VERSION 5.6 ;

BUSBITCHARS "[]" ;

DIVIDERCHAR "/" ;

UNITS
    DATABASE MICRONS 1000 ;
END UNITS

MANUFACTURINGGRID 0.005000 ; 

CLEARANCEMEASURE EUCLIDEAN ; 

USEMINSPACING OBS ON ; 

SITE CoreSite
    CLASS CORE ;
    SIZE 0.600000 BY 0.300000 ;
END CoreSite

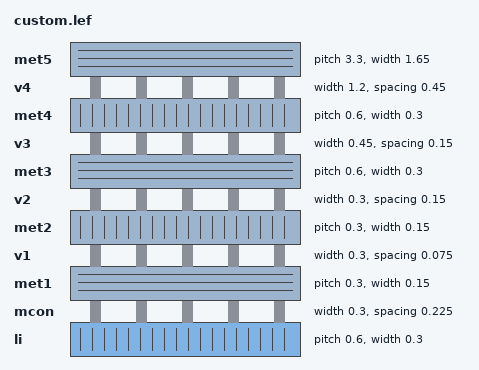
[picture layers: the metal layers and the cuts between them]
LAYER li
   TYPE ROUTING ;
   DIRECTION VERTICAL ;
   MINWIDTH 0.300000 ;
   AREA 0.056250 ;
   WIDTH 0.300000 ;
   SPACINGTABLE
      PARALLELRUNLENGTH 0.0
      WIDTH 0.0 0.225000 ;
   PITCH 0.600000 0.600000 ;
END li

LAYER mcon
    TYPE CUT ;
    SPACING 0.225000 ;
    WIDTH 0.300000 ;
    ENCLOSURE ABOVE 0.075000 0.075000 ;
    ENCLOSURE BELOW 0.000000 0.000000 ;
END mcon

LAYER met1
   TYPE ROUTING ;
   DIRECTION HORIZONTAL ;
   MINWIDTH 0.150000 ;
   AREA 0.084375 ;
   WIDTH 0.150000 ;
   SPACINGTABLE
      PARALLELRUNLENGTH 0.0
      WIDTH 0.0 0.150000 ;
   PITCH 0.300000 0.300000 ;
END met1

LAYER v1
    TYPE CUT ;
    SPACING 0.075000 ;
    WIDTH 0.300000 ;
    ENCLOSURE ABOVE 0.075000 0.075000 ;
    ENCLOSURE BELOW 0.075000 0.075000 ;
END v1

LAYER met2
   TYPE ROUTING ;
   DIRECTION VERTICAL ;
   MINWIDTH 0.150000 ;
   AREA 0.073125 ;
   WIDTH 0.150000 ;
   SPACINGTABLE
      PARALLELRUNLENGTH 0.0
      WIDTH 0.0 0.150000 ;
   PITCH 0.300000 0.300000 ;
END met2

LAYER v2
    TYPE CUT ;
    SPACING 0.150000 ;
    WIDTH 0.300000 ;
    ENCLOSURE ABOVE 0.075000 0.075000 ;
    ENCLOSURE BELOW 0.075000 0.000000 ;
END v2

LAYER met3
   TYPE ROUTING ;
   DIRECTION HORIZONTAL ;
   MINWIDTH 0.300000 ;
   AREA 0.241875 ;
   WIDTH 0.300000 ;
   SPACINGTABLE
      PARALLELRUNLENGTH 0.0
      WIDTH 0.0 0.300000 ;
   PITCH 0.600000 0.600000 ;
END met3

LAYER v3
    TYPE CUT ;
    SPACING 0.150000 ;
    WIDTH 0.450000 ;
    ENCLOSURE ABOVE 0.075000 0.075000 ;
    ENCLOSURE BELOW 0.075000 0.000000 ;
END v3

LAYER met4
   TYPE ROUTING ;
   DIRECTION VERTICAL ;
   MINWIDTH 0.300000 ;
   AREA 0.241875 ;
   WIDTH 0.300000 ;
   SPACINGTABLE
      PARALLELRUNLENGTH 0.0
      WIDTH 0.0 0.300000 ;
   PITCH 0.600000 0.600000 ;
END met4

LAYER v4
    TYPE CUT ;
    SPACING 0.450000 ;
    WIDTH 1.200000 ;
    ENCLOSURE ABOVE 0.150000 0.150000 ;
    ENCLOSURE BELOW 0.000000 0.000000 ;
END v4

LAYER met5
   TYPE ROUTING ;
   DIRECTION HORIZONTAL ;
   MINWIDTH 1.650000 ;
   AREA 4.005000 ;
   WIDTH 1.650000 ;
   SPACINGTABLE
      PARALLELRUNLENGTH 0.0
      WIDTH 0.0 1.650000 ;
   PITCH 3.300000 3.300000 ;
END met5

LAYER OVERLAP
   TYPE OVERLAP ;
END OVERLAP

VIA mcon_C DEFAULT
   LAYER li ;
     RECT -0.150000 -0.150000 0.150000 0.150000 ;
   LAYER mcon ;
     RECT -0.150000 -0.150000 0.150000 0.150000 ;
   LAYER met1 ;
     RECT -0.225000 -0.225000 0.225000 0.225000 ;
END mcon_C

VIA v1_C DEFAULT
   LAYER met1 ;
     RECT -0.225000 -0.225000 0.225000 0.225000 ;
   LAYER v1 ;
     RECT -0.150000 -0.150000 0.150000 0.150000 ;
   LAYER met2 ;
     RECT -0.225000 -0.225000 0.225000 0.225000 ;
END v1_C

VIA v2_C DEFAULT
   LAYER met2 ;
     RECT -0.150000 -0.225000 0.150000 0.225000 ;
   LAYER v2 ;
     RECT -0.150000 -0.150000 0.150000 0.150000 ;
   LAYER met3 ;
     RECT -0.225000 -0.225000 0.225000 0.225000 ;
END v2_C

VIA v2_Ch
   LAYER met2 ;
     RECT -0.225000 -0.150000 0.225000 0.150000 ;
   LAYER v2 ;
     RECT -0.150000 -0.150000 0.150000 0.150000 ;
   LAYER met3 ;
     RECT -0.225000 -0.225000 0.225000 0.225000 ;
END v2_Ch

VIA v2_Cv
   LAYER met2 ;
     RECT -0.150000 -0.225000 0.150000 0.225000 ;
   LAYER v2 ;
     RECT -0.150000 -0.150000 0.150000 0.150000 ;
   LAYER met3 ;
     RECT -0.225000 -0.225000 0.225000 0.225000 ;
END v2_Cv

VIA v3_C DEFAULT
   LAYER met3 ;
     RECT -0.300000 -0.225000 0.300000 0.225000 ;
   LAYER v3 ;
     RECT -0.225000 -0.225000 0.225000 0.225000 ;
   LAYER met4 ;
     RECT -0.300000 -0.300000 0.300000 0.300000 ;
END v3_C

VIA v3_Ch
   LAYER met3 ;
     RECT -0.300000 -0.225000 0.300000 0.225000 ;
   LAYER v3 ;
     RECT -0.225000 -0.225000 0.225000 0.225000 ;
   LAYER met4 ;
     RECT -0.300000 -0.300000 0.300000 0.300000 ;
END v3_Ch

VIA v3_Cv
   LAYER met3 ;
     RECT -0.300000 -0.225000 0.300000 0.225000 ;
   LAYER v3 ;
     RECT -0.225000 -0.225000 0.225000 0.225000 ;
   LAYER met4 ;
     RECT -0.300000 -0.300000 0.300000 0.300000 ;
END v3_Cv

VIA v4_C DEFAULT
   LAYER met4 ;
     RECT -0.600000 -0.600000 0.600000 0.600000 ;
   LAYER v4 ;
     RECT -0.600000 -0.600000 0.600000 0.600000 ;
   LAYER met5 ;
     RECT -0.750000 -0.750000 0.750000 0.750000 ;
END v4_C

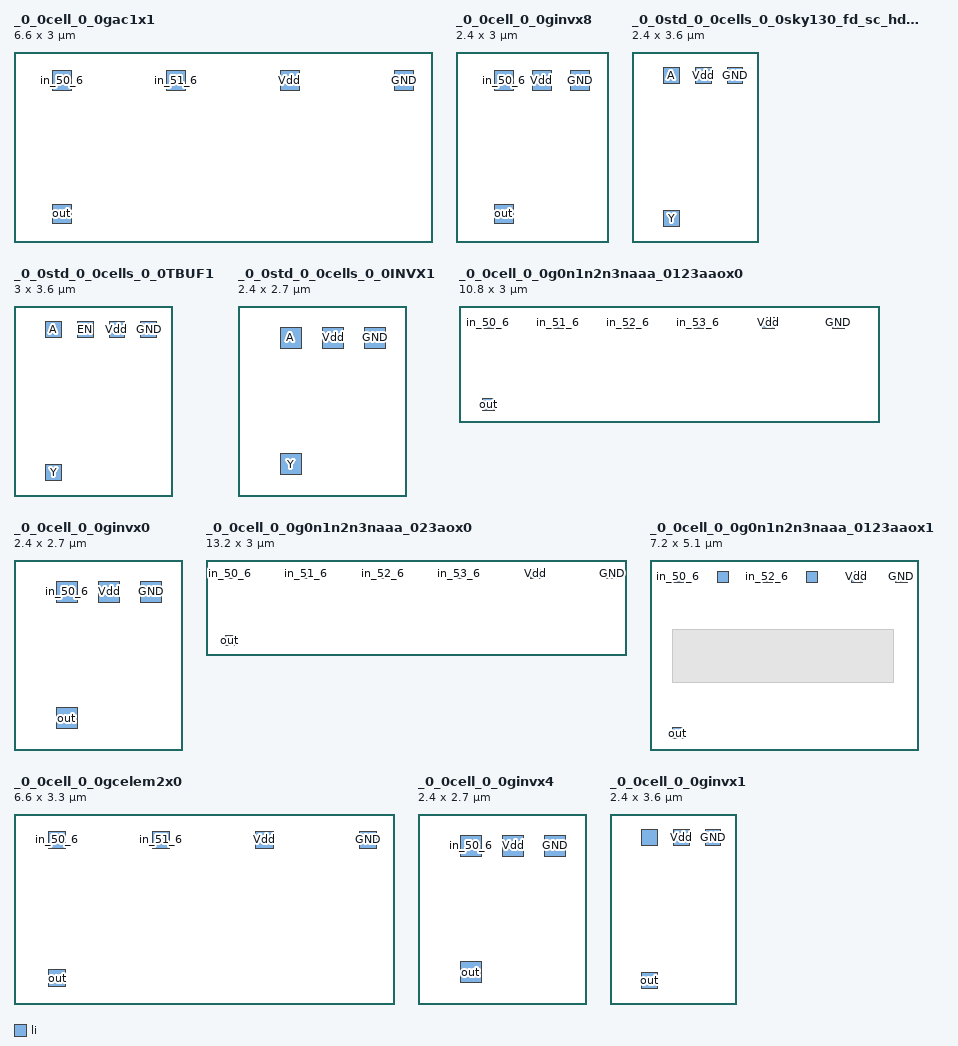
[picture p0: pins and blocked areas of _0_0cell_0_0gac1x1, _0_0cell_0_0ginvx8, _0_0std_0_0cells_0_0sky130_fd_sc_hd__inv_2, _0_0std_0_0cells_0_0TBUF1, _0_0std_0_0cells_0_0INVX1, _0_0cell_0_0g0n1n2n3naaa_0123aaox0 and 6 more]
MACRO _0_0cell_0_0gac1x1
    CLASS CORE ;
    FOREIGN _0_0cell_0_0gac1x1 0.000000 0.000000 ;
    ORIGIN 0.000000 0.000000 ;
    SIZE 6.600000 BY 3.000000 ;
    SYMMETRY X Y ;
    SITE CoreSite ;
    PIN in_50_6
        DIRECTION INPUT ;
        USE SIGNAL ;
        PORT
        LAYER li ;
        RECT 0.600000 2.400000 0.900000 2.700000 ;
        END
    END in_50_6
    PIN in_51_6
        DIRECTION INPUT ;
        USE SIGNAL ;
        PORT
        LAYER li ;
        RECT 2.400000 2.400000 2.700000 2.700000 ;
        END
    END in_51_6
    PIN out
        DIRECTION OUTPUT ;
        USE SIGNAL ;
        PORT
        LAYER li ;
        RECT 0.600000 0.300000 0.900000 0.600000 ;
        END
        ANTENNADIFFAREA 0.787500 ;
    END out
    PIN Vdd
        DIRECTION INPUT ;
        USE POWER ;
        PORT
        LAYER li ;
        RECT 4.200000 2.400000 4.500000 2.700000 ;
        END
        ANTENNADIFFAREA 0.450000 ;
    END Vdd
    PIN GND
        DIRECTION INPUT ;
        USE GROUND ;
        PORT
        LAYER li ;
        RECT 6.000000 2.400000 6.300000 2.700000 ;
        END
        ANTENNADIFFAREA 0.337500 ;
    END GND
END _0_0cell_0_0gac1x1

MACRO _0_0cell_0_0ginvx8
    CLASS CORE ;
    FOREIGN _0_0cell_0_0ginvx8 0.000000 0.000000 ;
    ORIGIN 0.000000 0.000000 ;
    SIZE 2.400000 BY 3.000000 ;
    SYMMETRY X Y ;
    SITE CoreSite ;
    PIN in_50_6
        DIRECTION INPUT ;
        USE SIGNAL ;
        PORT
        LAYER li ;
        RECT 0.600000 2.400000 0.900000 2.700000 ;
        END
    END in_50_6
    PIN out
        DIRECTION OUTPUT ;
        USE SIGNAL ;
        PORT
        LAYER li ;
        RECT 0.600000 0.300000 0.900000 0.600000 ;
        END
        ANTENNADIFFAREA 0.450000 ;
    END out
    PIN Vdd
        DIRECTION INPUT ;
        USE POWER ;
        PORT
        LAYER li ;
        RECT 1.200000 2.400000 1.500000 2.700000 ;
        END
        ANTENNADIFFAREA 0.281250 ;
    END Vdd
    PIN GND
        DIRECTION INPUT ;
        USE GROUND ;
        PORT
        LAYER li ;
        RECT 1.800000 2.400000 2.100000 2.700000 ;
        END
        ANTENNADIFFAREA 0.168750 ;
    END GND
END _0_0cell_0_0ginvx8

MACRO _0_0std_0_0cells_0_0sky130_fd_sc_hd__inv_2
    CLASS CORE ;
    FOREIGN _0_0std_0_0cells_0_0sky130_fd_sc_hd__inv_2 0.000000 0.000000 ;
    ORIGIN 0.000000 0.000000 ;
    SIZE 2.400000 BY 3.600000 ;
    SYMMETRY X Y ;
    SITE CoreSite ;
    PIN A
        DIRECTION INPUT ;
        USE SIGNAL ;
        PORT
        LAYER li ;
        RECT 0.600000 3.000000 0.900000 3.300000 ;
        END
    END A
    PIN Y
        DIRECTION OUTPUT ;
        USE SIGNAL ;
        PORT
        LAYER li ;
        RECT 0.600000 0.300000 0.900000 0.600000 ;
        END
        ANTENNADIFFAREA 0.703125 ;
    END Y
    PIN Vdd
        DIRECTION INPUT ;
        USE POWER ;
        PORT
        LAYER li ;
        RECT 1.200000 3.000000 1.500000 3.300000 ;
        END
        ANTENNADIFFAREA 0.421875 ;
    END Vdd
    PIN GND
        DIRECTION INPUT ;
        USE GROUND ;
        PORT
        LAYER li ;
        RECT 1.800000 3.000000 2.100000 3.300000 ;
        END
        ANTENNADIFFAREA 0.281250 ;
    END GND
END _0_0std_0_0cells_0_0sky130_fd_sc_hd__inv_2

MACRO _0_0std_0_0cells_0_0TBUF1
    CLASS CORE ;
    FOREIGN _0_0std_0_0cells_0_0TBUF1 0.000000 0.000000 ;
    ORIGIN 0.000000 0.000000 ;
    SIZE 3.000000 BY 3.600000 ;
    SYMMETRY X Y ;
    SITE CoreSite ;
    PIN A
        DIRECTION INPUT ;
        USE SIGNAL ;
        PORT
        LAYER li ;
        RECT 0.600000 3.000000 0.900000 3.300000 ;
        END
    END A
    PIN EN
        DIRECTION INPUT ;
        USE SIGNAL ;
        PORT
        LAYER li ;
        RECT 1.200000 3.000000 1.500000 3.300000 ;
        END
    END EN
    PIN Y
        DIRECTION OUTPUT ;
        USE SIGNAL ;
        PORT
        LAYER li ;
        RECT 0.600000 0.300000 0.900000 0.600000 ;
        END
        ANTENNADIFFAREA 0.703125 ;
    END Y
    PIN Vdd
        DIRECTION INPUT ;
        USE POWER ;
        PORT
        LAYER li ;
        RECT 1.800000 3.000000 2.100000 3.300000 ;
        END
        ANTENNADIFFAREA 0.337500 ;
    END Vdd
    PIN GND
        DIRECTION INPUT ;
        USE GROUND ;
        PORT
        LAYER li ;
        RECT 2.400000 3.000000 2.700000 3.300000 ;
        END
        ANTENNADIFFAREA 0.101250 ;
    END GND
END _0_0std_0_0cells_0_0TBUF1

MACRO _0_0std_0_0cells_0_0INVX1
    CLASS CORE ;
    FOREIGN _0_0std_0_0cells_0_0INVX1 0.000000 0.000000 ;
    ORIGIN 0.000000 0.000000 ;
    SIZE 2.400000 BY 2.700000 ;
    SYMMETRY X Y ;
    SITE CoreSite ;
    PIN A
        DIRECTION INPUT ;
        USE SIGNAL ;
        PORT
        LAYER li ;
        RECT 0.600000 2.100000 0.900000 2.400000 ;
        END
    END A
    PIN Y
        DIRECTION OUTPUT ;
        USE SIGNAL ;
        PORT
        LAYER li ;
        RECT 0.600000 0.300000 0.900000 0.600000 ;
        END
        ANTENNADIFFAREA 0.393750 ;
    END Y
    PIN Vdd
        DIRECTION INPUT ;
        USE POWER ;
        PORT
        LAYER li ;
        RECT 1.200000 2.100000 1.500000 2.400000 ;
        END
        ANTENNADIFFAREA 0.225000 ;
    END Vdd
    PIN GND
        DIRECTION INPUT ;
        USE GROUND ;
        PORT
        LAYER li ;
        RECT 1.800000 2.100000 2.100000 2.400000 ;
        END
        ANTENNADIFFAREA 0.168750 ;
    END GND
END _0_0std_0_0cells_0_0INVX1

MACRO _0_0cell_0_0g0n1n2n3naaa_0123aaox0
    CLASS CORE ;
    FOREIGN _0_0cell_0_0g0n1n2n3naaa_0123aaox0 0.000000 0.000000 ;
    ORIGIN 0.000000 0.000000 ;
    SIZE 10.800000 BY 3.000000 ;
    SYMMETRY X Y ;
    SITE CoreSite ;
    PIN in_50_6
        DIRECTION INPUT ;
        USE SIGNAL ;
        PORT
        LAYER li ;
        RECT 0.600000 2.400000 0.900000 2.700000 ;
        END
    END in_50_6
    PIN in_51_6
        DIRECTION INPUT ;
        USE SIGNAL ;
        PORT
        LAYER li ;
        RECT 2.400000 2.400000 2.700000 2.700000 ;
        END
    END in_51_6
    PIN in_52_6
        DIRECTION INPUT ;
        USE SIGNAL ;
        PORT
        LAYER li ;
        RECT 4.200000 2.400000 4.500000 2.700000 ;
        END
    END in_52_6
    PIN in_53_6
        DIRECTION INPUT ;
        USE SIGNAL ;
        PORT
        LAYER li ;
        RECT 6.000000 2.400000 6.300000 2.700000 ;
        END
    END in_53_6
    PIN out
        DIRECTION OUTPUT ;
        USE SIGNAL ;
        PORT
        LAYER li ;
        RECT 0.600000 0.300000 0.900000 0.600000 ;
        END
        ANTENNADIFFAREA 0.506250 ;
    END out
    PIN Vdd
        DIRECTION INPUT ;
        USE POWER ;
        PORT
        LAYER li ;
        RECT 7.800000 2.400000 8.100000 2.700000 ;
        END
        ANTENNADIFFAREA 0.731250 ;
    END Vdd
    PIN GND
        DIRECTION INPUT ;
        USE GROUND ;
        PORT
        LAYER li ;
        RECT 9.600000 2.400000 9.900000 2.700000 ;
        END
        ANTENNADIFFAREA 0.506250 ;
    END GND
END _0_0cell_0_0g0n1n2n3naaa_0123aaox0

MACRO _0_0cell_0_0ginvx0
    CLASS CORE ;
    FOREIGN _0_0cell_0_0ginvx0 0.000000 0.000000 ;
    ORIGIN 0.000000 0.000000 ;
    SIZE 2.400000 BY 2.700000 ;
    SYMMETRY X Y ;
    SITE CoreSite ;
    PIN in_50_6
        DIRECTION INPUT ;
        USE SIGNAL ;
        PORT
        LAYER li ;
        RECT 0.600000 2.100000 0.900000 2.400000 ;
        END
    END in_50_6
    PIN out
        DIRECTION OUTPUT ;
        USE SIGNAL ;
        PORT
        LAYER li ;
        RECT 0.600000 0.300000 0.900000 0.600000 ;
        END
        ANTENNADIFFAREA 0.393750 ;
    END out
    PIN Vdd
        DIRECTION INPUT ;
        USE POWER ;
        PORT
        LAYER li ;
        RECT 1.200000 2.100000 1.500000 2.400000 ;
        END
        ANTENNADIFFAREA 0.225000 ;
    END Vdd
    PIN GND
        DIRECTION INPUT ;
        USE GROUND ;
        PORT
        LAYER li ;
        RECT 1.800000 2.100000 2.100000 2.400000 ;
        END
        ANTENNADIFFAREA 0.168750 ;
    END GND
END _0_0cell_0_0ginvx0

MACRO _0_0cell_0_0g0n1n2n3naaa_023aox0
    CLASS CORE ;
    FOREIGN _0_0cell_0_0g0n1n2n3naaa_023aox0 0.000000 0.000000 ;
    ORIGIN 0.000000 0.000000 ;
    SIZE 13.200000 BY 3.000000 ;
    SYMMETRY X Y ;
    SITE CoreSite ;
    PIN in_50_6
        DIRECTION INPUT ;
        USE SIGNAL ;
        PORT
        LAYER li ;
        RECT 0.600000 2.400000 0.900000 2.700000 ;
        END
    END in_50_6
    PIN in_51_6
        DIRECTION INPUT ;
        USE SIGNAL ;
        PORT
        LAYER li ;
        RECT 3.000000 2.400000 3.300000 2.700000 ;
        END
    END in_51_6
    PIN in_52_6
        DIRECTION INPUT ;
        USE SIGNAL ;
        PORT
        LAYER li ;
        RECT 5.400000 2.400000 5.700000 2.700000 ;
        END
    END in_52_6
    PIN in_53_6
        DIRECTION INPUT ;
        USE SIGNAL ;
        PORT
        LAYER li ;
        RECT 7.800000 2.400000 8.100000 2.700000 ;
        END
    END in_53_6
    PIN out
        DIRECTION OUTPUT ;
        USE SIGNAL ;
        PORT
        LAYER li ;
        RECT 0.600000 0.300000 0.900000 0.600000 ;
        END
        ANTENNADIFFAREA 0.562500 ;
    END out
    PIN Vdd
        DIRECTION INPUT ;
        USE POWER ;
        PORT
        LAYER li ;
        RECT 10.200000 2.400000 10.500000 2.700000 ;
        END
        ANTENNADIFFAREA 0.450000 ;
    END Vdd
    PIN GND
        DIRECTION INPUT ;
        USE GROUND ;
        PORT
        LAYER li ;
        RECT 12.600000 2.400000 12.900000 2.700000 ;
        END
        ANTENNADIFFAREA 0.337500 ;
    END GND
END _0_0cell_0_0g0n1n2n3naaa_023aox0

MACRO _0_0cell_0_0g0n1n2n3naaa_0123aaox1
    CLASS CORE ;
    FOREIGN _0_0cell_0_0g0n1n2n3naaa_0123aaox1 0.000000 0.000000 ;
    ORIGIN 0.000000 0.000000 ;
    SIZE 7.200000 BY 5.100000 ;
    SYMMETRY X Y ;
    SITE CoreSite ;
    PIN in_50_6
        DIRECTION INPUT ;
        USE SIGNAL ;
        PORT
        LAYER li ;
        RECT 0.600000 4.500000 0.900000 4.800000 ;
        END
    END in_50_6
    PIN in_51_6
        DIRECTION INPUT ;
        USE SIGNAL ;
        PORT
        LAYER li ;
        RECT 1.800000 4.500000 2.100000 4.800000 ;
        END
    END in_51_6
    PIN in_52_6
        DIRECTION INPUT ;
        USE SIGNAL ;
        PORT
        LAYER li ;
        RECT 3.000000 4.500000 3.300000 4.800000 ;
        END
    END in_52_6
    PIN in_53_6
        DIRECTION INPUT ;
        USE SIGNAL ;
        PORT
        LAYER li ;
        RECT 4.200000 4.500000 4.500000 4.800000 ;
        END
    END in_53_6
    PIN out
        DIRECTION OUTPUT ;
        USE SIGNAL ;
        PORT
        LAYER li ;
        RECT 0.600000 0.300000 0.900000 0.600000 ;
        END
        ANTENNADIFFAREA 0.371250 ;
    END out
    PIN Vdd
        DIRECTION INPUT ;
        USE POWER ;
        PORT
        LAYER li ;
        RECT 5.400000 4.500000 5.700000 4.800000 ;
        END
        ANTENNADIFFAREA 1.293750 ;
    END Vdd
    PIN GND
        DIRECTION INPUT ;
        USE GROUND ;
        PORT
        LAYER li ;
        RECT 6.600000 4.500000 6.900000 4.800000 ;
        END
        ANTENNADIFFAREA 0.675000 ;
    END GND
    OBS
      LAYER li ;
         RECT 0.600000 1.800000 6.525000 3.225000 ;
    END
END _0_0cell_0_0g0n1n2n3naaa_0123aaox1

MACRO _0_0cell_0_0gcelem2x0
    CLASS CORE ;
    FOREIGN _0_0cell_0_0gcelem2x0 0.000000 0.000000 ;
    ORIGIN 0.000000 0.000000 ;
    SIZE 6.600000 BY 3.300000 ;
    SYMMETRY X Y ;
    SITE CoreSite ;
    PIN in_50_6
        DIRECTION INPUT ;
        USE SIGNAL ;
        PORT
        LAYER li ;
        RECT 0.600000 2.700000 0.900000 3.000000 ;
        END
    END in_50_6
    PIN in_51_6
        DIRECTION INPUT ;
        USE SIGNAL ;
        PORT
        LAYER li ;
        RECT 2.400000 2.700000 2.700000 3.000000 ;
        END
    END in_51_6
    PIN out
        DIRECTION OUTPUT ;
        USE SIGNAL ;
        PORT
        LAYER li ;
        RECT 0.600000 0.300000 0.900000 0.600000 ;
        END
        ANTENNADIFFAREA 0.202500 ;
    END out
    PIN Vdd
        DIRECTION INPUT ;
        USE POWER ;
        PORT
        LAYER li ;
        RECT 4.200000 2.700000 4.500000 3.000000 ;
        END
        ANTENNADIFFAREA 0.438750 ;
    END Vdd
    PIN GND
        DIRECTION INPUT ;
        USE GROUND ;
        PORT
        LAYER li ;
        RECT 6.000000 2.700000 6.300000 3.000000 ;
        END
        ANTENNADIFFAREA 0.393750 ;
    END GND
END _0_0cell_0_0gcelem2x0

MACRO _0_0cell_0_0ginvx4
    CLASS CORE ;
    FOREIGN _0_0cell_0_0ginvx4 0.000000 0.000000 ;
    ORIGIN 0.000000 0.000000 ;
    SIZE 2.400000 BY 2.700000 ;
    SYMMETRY X Y ;
    SITE CoreSite ;
    PIN in_50_6
        DIRECTION INPUT ;
        USE SIGNAL ;
        PORT
        LAYER li ;
        RECT 0.600000 2.100000 0.900000 2.400000 ;
        END
    END in_50_6
    PIN out
        DIRECTION OUTPUT ;
        USE SIGNAL ;
        PORT
        LAYER li ;
        RECT 0.600000 0.300000 0.900000 0.600000 ;
        END
        ANTENNADIFFAREA 0.337500 ;
    END out
    PIN Vdd
        DIRECTION INPUT ;
        USE POWER ;
        PORT
        LAYER li ;
        RECT 1.200000 2.100000 1.500000 2.400000 ;
        END
        ANTENNADIFFAREA 0.168750 ;
    END Vdd
    PIN GND
        DIRECTION INPUT ;
        USE GROUND ;
        PORT
        LAYER li ;
        RECT 1.800000 2.100000 2.100000 2.400000 ;
        END
        ANTENNADIFFAREA 0.168750 ;
    END GND
END _0_0cell_0_0ginvx4

MACRO _0_0cell_0_0ginvx1
    CLASS CORE ;
    FOREIGN _0_0cell_0_0ginvx1 0.000000 0.000000 ;
    ORIGIN 0.000000 0.000000 ;
    SIZE 2.400000 BY 3.600000 ;
    SYMMETRY X Y ;
    SITE CoreSite ;
    PIN in_50_6
        DIRECTION INPUT ;
        USE SIGNAL ;
        PORT
        LAYER li ;
        RECT 0.600000 3.000000 0.900000 3.300000 ;
        END
    END in_50_6
    PIN out
        DIRECTION OUTPUT ;
        USE SIGNAL ;
        PORT
        LAYER li ;
        RECT 0.600000 0.300000 0.900000 0.600000 ;
        END
        ANTENNADIFFAREA 0.703125 ;
    END out
    PIN Vdd
        DIRECTION INPUT ;
        USE POWER ;
        PORT
        LAYER li ;
        RECT 1.200000 3.000000 1.500000 3.300000 ;
        END
        ANTENNADIFFAREA 0.421875 ;
    END Vdd
    PIN GND
        DIRECTION INPUT ;
        USE GROUND ;
        PORT
        LAYER li ;
        RECT 1.800000 3.000000 2.100000 3.300000 ;
        END
        ANTENNADIFFAREA 0.281250 ;
    END GND
END _0_0cell_0_0ginvx1

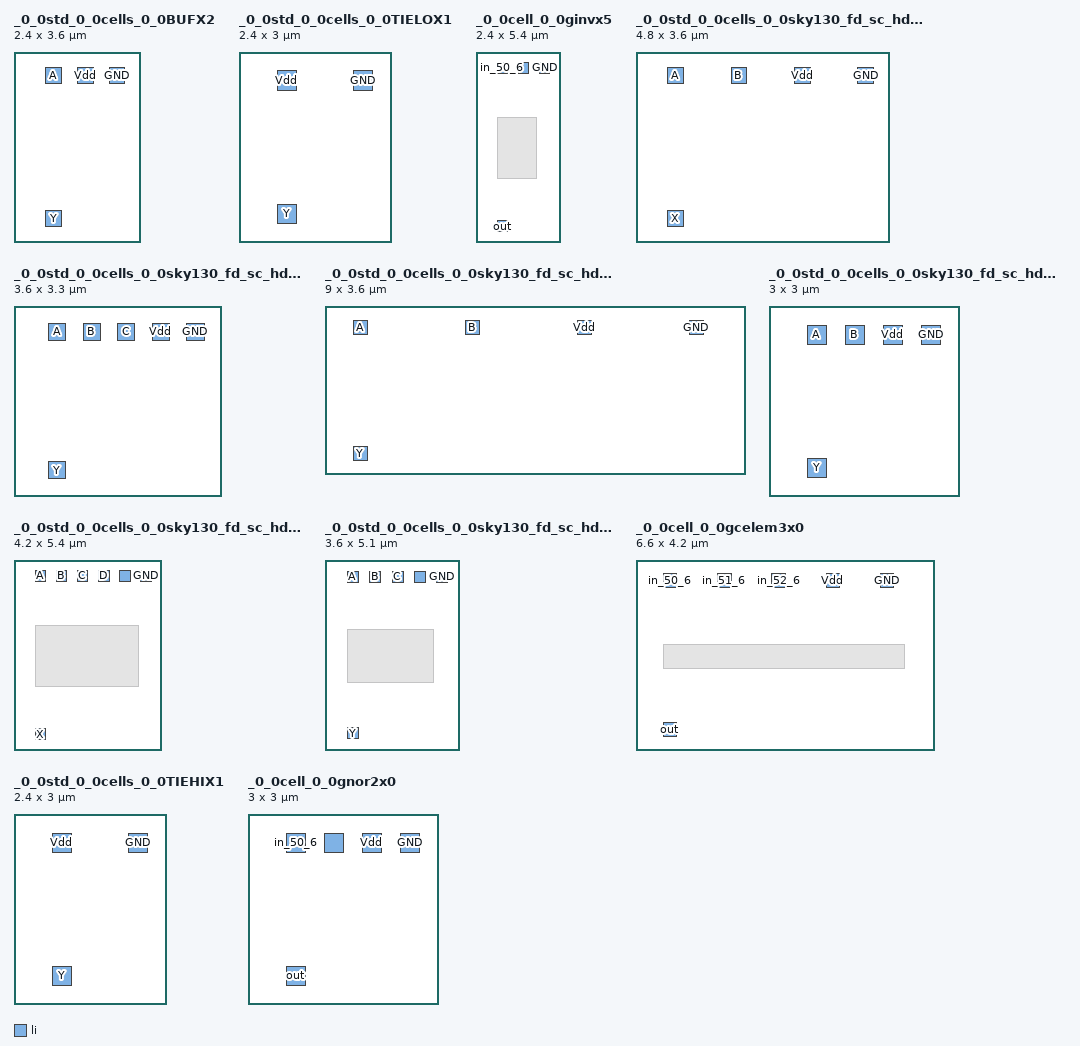
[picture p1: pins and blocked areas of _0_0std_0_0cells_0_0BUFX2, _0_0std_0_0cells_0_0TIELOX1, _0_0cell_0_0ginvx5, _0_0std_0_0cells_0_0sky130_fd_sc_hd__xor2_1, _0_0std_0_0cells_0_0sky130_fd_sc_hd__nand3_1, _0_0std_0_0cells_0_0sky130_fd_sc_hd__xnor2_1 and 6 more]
MACRO _0_0std_0_0cells_0_0BUFX2
    CLASS CORE ;
    FOREIGN _0_0std_0_0cells_0_0BUFX2 0.000000 0.000000 ;
    ORIGIN 0.000000 0.000000 ;
    SIZE 2.400000 BY 3.600000 ;
    SYMMETRY X Y ;
    SITE CoreSite ;
    PIN A
        DIRECTION INPUT ;
        USE SIGNAL ;
        PORT
        LAYER li ;
        RECT 0.600000 3.000000 0.900000 3.300000 ;
        END
    END A
    PIN Y
        DIRECTION OUTPUT ;
        USE SIGNAL ;
        PORT
        LAYER li ;
        RECT 0.600000 0.300000 0.900000 0.600000 ;
        END
        ANTENNADIFFAREA 0.703125 ;
    END Y
    PIN Vdd
        DIRECTION INPUT ;
        USE POWER ;
        PORT
        LAYER li ;
        RECT 1.200000 3.000000 1.500000 3.300000 ;
        END
        ANTENNADIFFAREA 0.337500 ;
    END Vdd
    PIN GND
        DIRECTION INPUT ;
        USE GROUND ;
        PORT
        LAYER li ;
        RECT 1.800000 3.000000 2.100000 3.300000 ;
        END
        ANTENNADIFFAREA 0.225000 ;
    END GND
END _0_0std_0_0cells_0_0BUFX2

MACRO _0_0std_0_0cells_0_0TIELOX1
    CLASS CORE ;
    FOREIGN _0_0std_0_0cells_0_0TIELOX1 0.000000 0.000000 ;
    ORIGIN 0.000000 0.000000 ;
    SIZE 2.400000 BY 3.000000 ;
    SYMMETRY X Y ;
    SITE CoreSite ;
    PIN Y
        DIRECTION OUTPUT ;
        USE SIGNAL ;
        PORT
        LAYER li ;
        RECT 0.600000 0.300000 0.900000 0.600000 ;
        END
        ANTENNADIFFAREA 0.168750 ;
    END Y
    PIN Vdd
        DIRECTION INPUT ;
        USE POWER ;
        PORT
        LAYER li ;
        RECT 0.600000 2.400000 0.900000 2.700000 ;
        END
        ANTENNADIFFAREA 0.281250 ;
    END Vdd
    PIN GND
        DIRECTION INPUT ;
        USE GROUND ;
        PORT
        LAYER li ;
        RECT 1.800000 2.400000 2.100000 2.700000 ;
        END
        ANTENNADIFFAREA 0.168750 ;
    END GND
END _0_0std_0_0cells_0_0TIELOX1

MACRO _0_0cell_0_0ginvx5
    CLASS CORE ;
    FOREIGN _0_0cell_0_0ginvx5 0.000000 0.000000 ;
    ORIGIN 0.000000 0.000000 ;
    SIZE 2.400000 BY 5.400000 ;
    SYMMETRY X Y ;
    SITE CoreSite ;
    PIN in_50_6
        DIRECTION INPUT ;
        USE SIGNAL ;
        PORT
        LAYER li ;
        RECT 0.600000 4.800000 0.900000 5.100000 ;
        END
    END in_50_6
    PIN out
        DIRECTION OUTPUT ;
        USE SIGNAL ;
        PORT
        LAYER li ;
        RECT 0.600000 0.300000 0.900000 0.600000 ;
        END
        ANTENNADIFFAREA 1.968750 ;
    END out
    PIN Vdd
        DIRECTION INPUT ;
        USE POWER ;
        PORT
        LAYER li ;
        RECT 1.200000 4.800000 1.500000 5.100000 ;
        END
        ANTENNADIFFAREA 1.687500 ;
    END Vdd
    PIN GND
        DIRECTION INPUT ;
        USE GROUND ;
        PORT
        LAYER li ;
        RECT 1.800000 4.800000 2.100000 5.100000 ;
        END
        ANTENNADIFFAREA 0.562500 ;
    END GND
    OBS
      LAYER li ;
         RECT 0.600000 1.800000 1.725000 3.525000 ;
    END
END _0_0cell_0_0ginvx5

MACRO _0_0std_0_0cells_0_0sky130_fd_sc_hd__xor2_1
    CLASS CORE ;
    FOREIGN _0_0std_0_0cells_0_0sky130_fd_sc_hd__xor2_1 0.000000 0.000000 ;
    ORIGIN 0.000000 0.000000 ;
    SIZE 4.800000 BY 3.600000 ;
    SYMMETRY X Y ;
    SITE CoreSite ;
    PIN A
        DIRECTION INPUT ;
        USE SIGNAL ;
        PORT
        LAYER li ;
        RECT 0.600000 3.000000 0.900000 3.300000 ;
        END
    END A
    PIN B
        DIRECTION INPUT ;
        USE SIGNAL ;
        PORT
        LAYER li ;
        RECT 1.800000 3.000000 2.100000 3.300000 ;
        END
    END B
    PIN X
        DIRECTION OUTPUT ;
        USE SIGNAL ;
        PORT
        LAYER li ;
        RECT 0.600000 0.300000 0.900000 0.600000 ;
        END
        ANTENNADIFFAREA 0.646875 ;
    END X
    PIN Vdd
        DIRECTION INPUT ;
        USE POWER ;
        PORT
        LAYER li ;
        RECT 3.000000 3.000000 3.300000 3.300000 ;
        END
        ANTENNADIFFAREA 0.421875 ;
    END Vdd
    PIN GND
        DIRECTION INPUT ;
        USE GROUND ;
        PORT
        LAYER li ;
        RECT 4.200000 3.000000 4.500000 3.300000 ;
        END
        ANTENNADIFFAREA 0.618750 ;
    END GND
END _0_0std_0_0cells_0_0sky130_fd_sc_hd__xor2_1

MACRO _0_0std_0_0cells_0_0sky130_fd_sc_hd__nand3_1
    CLASS CORE ;
    FOREIGN _0_0std_0_0cells_0_0sky130_fd_sc_hd__nand3_1 0.000000 0.000000 ;
    ORIGIN 0.000000 0.000000 ;
    SIZE 3.600000 BY 3.300000 ;
    SYMMETRY X Y ;
    SITE CoreSite ;
    PIN A
        DIRECTION INPUT ;
        USE SIGNAL ;
        PORT
        LAYER li ;
        RECT 0.600000 2.700000 0.900000 3.000000 ;
        END
    END A
    PIN B
        DIRECTION INPUT ;
        USE SIGNAL ;
        PORT
        LAYER li ;
        RECT 1.200000 2.700000 1.500000 3.000000 ;
        END
    END B
    PIN C
        DIRECTION INPUT ;
        USE SIGNAL ;
        PORT
        LAYER li ;
        RECT 1.800000 2.700000 2.100000 3.000000 ;
        END
    END C
    PIN Y
        DIRECTION OUTPUT ;
        USE SIGNAL ;
        PORT
        LAYER li ;
        RECT 0.600000 0.300000 0.900000 0.600000 ;
        END
        ANTENNADIFFAREA 0.871875 ;
    END Y
    PIN Vdd
        DIRECTION INPUT ;
        USE POWER ;
        PORT
        LAYER li ;
        RECT 2.400000 2.700000 2.700000 3.000000 ;
        END
        ANTENNADIFFAREA 0.450000 ;
    END Vdd
    PIN GND
        DIRECTION INPUT ;
        USE GROUND ;
        PORT
        LAYER li ;
        RECT 3.000000 2.700000 3.300000 3.000000 ;
        END
        ANTENNADIFFAREA 0.421875 ;
    END GND
END _0_0std_0_0cells_0_0sky130_fd_sc_hd__nand3_1

MACRO _0_0std_0_0cells_0_0sky130_fd_sc_hd__xnor2_1
    CLASS CORE ;
    FOREIGN _0_0std_0_0cells_0_0sky130_fd_sc_hd__xnor2_1 0.000000 0.000000 ;
    ORIGIN 0.000000 0.000000 ;
    SIZE 9.000000 BY 3.600000 ;
    SYMMETRY X Y ;
    SITE CoreSite ;
    PIN A
        DIRECTION INPUT ;
        USE SIGNAL ;
        PORT
        LAYER li ;
        RECT 0.600000 3.000000 0.900000 3.300000 ;
        END
    END A
    PIN B
        DIRECTION INPUT ;
        USE SIGNAL ;
        PORT
        LAYER li ;
        RECT 3.000000 3.000000 3.300000 3.300000 ;
        END
    END B
    PIN Y
        DIRECTION OUTPUT ;
        USE SIGNAL ;
        PORT
        LAYER li ;
        RECT 0.600000 0.300000 0.900000 0.600000 ;
        END
        ANTENNADIFFAREA 0.416250 ;
    END Y
    PIN Vdd
        DIRECTION INPUT ;
        USE POWER ;
        PORT
        LAYER li ;
        RECT 5.400000 3.000000 5.700000 3.300000 ;
        END
        ANTENNADIFFAREA 0.787500 ;
    END Vdd
    PIN GND
        DIRECTION INPUT ;
        USE GROUND ;
        PORT
        LAYER li ;
        RECT 7.800000 3.000000 8.100000 3.300000 ;
        END
        ANTENNADIFFAREA 0.675000 ;
    END GND
END _0_0std_0_0cells_0_0sky130_fd_sc_hd__xnor2_1

MACRO _0_0std_0_0cells_0_0sky130_fd_sc_hd__nand2_1
    CLASS CORE ;
    FOREIGN _0_0std_0_0cells_0_0sky130_fd_sc_hd__nand2_1 0.000000 0.000000 ;
    ORIGIN 0.000000 0.000000 ;
    SIZE 3.000000 BY 3.000000 ;
    SYMMETRY X Y ;
    SITE CoreSite ;
    PIN A
        DIRECTION INPUT ;
        USE SIGNAL ;
        PORT
        LAYER li ;
        RECT 0.600000 2.400000 0.900000 2.700000 ;
        END
    END A
    PIN B
        DIRECTION INPUT ;
        USE SIGNAL ;
        PORT
        LAYER li ;
        RECT 1.200000 2.400000 1.500000 2.700000 ;
        END
    END B
    PIN Y
        DIRECTION OUTPUT ;
        USE SIGNAL ;
        PORT
        LAYER li ;
        RECT 0.600000 0.300000 0.900000 0.600000 ;
        END
        ANTENNADIFFAREA 0.506250 ;
    END Y
    PIN Vdd
        DIRECTION INPUT ;
        USE POWER ;
        PORT
        LAYER li ;
        RECT 1.800000 2.400000 2.100000 2.700000 ;
        END
        ANTENNADIFFAREA 0.450000 ;
    END Vdd
    PIN GND
        DIRECTION INPUT ;
        USE GROUND ;
        PORT
        LAYER li ;
        RECT 2.400000 2.400000 2.700000 2.700000 ;
        END
        ANTENNADIFFAREA 0.281250 ;
    END GND
END _0_0std_0_0cells_0_0sky130_fd_sc_hd__nand2_1

MACRO _0_0std_0_0cells_0_0sky130_fd_sc_hd__and4_4
    CLASS CORE ;
    FOREIGN _0_0std_0_0cells_0_0sky130_fd_sc_hd__and4_4 0.000000 0.000000 ;
    ORIGIN 0.000000 0.000000 ;
    SIZE 4.200000 BY 5.400000 ;
    SYMMETRY X Y ;
    SITE CoreSite ;
    PIN A
        DIRECTION INPUT ;
        USE SIGNAL ;
        PORT
        LAYER li ;
        RECT 0.600000 4.800000 0.900000 5.100000 ;
        END
    END A
    PIN B
        DIRECTION INPUT ;
        USE SIGNAL ;
        PORT
        LAYER li ;
        RECT 1.200000 4.800000 1.500000 5.100000 ;
        END
    END B
    PIN C
        DIRECTION INPUT ;
        USE SIGNAL ;
        PORT
        LAYER li ;
        RECT 1.800000 4.800000 2.100000 5.100000 ;
        END
    END C
    PIN D
        DIRECTION INPUT ;
        USE SIGNAL ;
        PORT
        LAYER li ;
        RECT 2.400000 4.800000 2.700000 5.100000 ;
        END
    END D
    PIN X
        DIRECTION OUTPUT ;
        USE SIGNAL ;
        PORT
        LAYER li ;
        RECT 0.600000 0.300000 0.900000 0.600000 ;
        END
        ANTENNADIFFAREA 1.406250 ;
    END X
    PIN Vdd
        DIRECTION INPUT ;
        USE POWER ;
        PORT
        LAYER li ;
        RECT 3.000000 4.800000 3.300000 5.100000 ;
        END
        ANTENNADIFFAREA 0.585000 ;
    END Vdd
    PIN GND
        DIRECTION INPUT ;
        USE GROUND ;
        PORT
        LAYER li ;
        RECT 3.600000 4.800000 3.900000 5.100000 ;
        END
        ANTENNADIFFAREA 0.787500 ;
    END GND
    OBS
      LAYER li ;
         RECT 0.600000 1.800000 3.525000 3.525000 ;
    END
END _0_0std_0_0cells_0_0sky130_fd_sc_hd__and4_4

MACRO _0_0std_0_0cells_0_0sky130_fd_sc_hd__nand3_2
    CLASS CORE ;
    FOREIGN _0_0std_0_0cells_0_0sky130_fd_sc_hd__nand3_2 0.000000 0.000000 ;
    ORIGIN 0.000000 0.000000 ;
    SIZE 3.600000 BY 5.100000 ;
    SYMMETRY X Y ;
    SITE CoreSite ;
    PIN A
        DIRECTION INPUT ;
        USE SIGNAL ;
        PORT
        LAYER li ;
        RECT 0.600000 4.500000 0.900000 4.800000 ;
        END
    END A
    PIN B
        DIRECTION INPUT ;
        USE SIGNAL ;
        PORT
        LAYER li ;
        RECT 1.200000 4.500000 1.500000 4.800000 ;
        END
    END B
    PIN C
        DIRECTION INPUT ;
        USE SIGNAL ;
        PORT
        LAYER li ;
        RECT 1.800000 4.500000 2.100000 4.800000 ;
        END
    END C
    PIN Y
        DIRECTION OUTPUT ;
        USE SIGNAL ;
        PORT
        LAYER li ;
        RECT 0.600000 0.300000 0.900000 0.600000 ;
        END
        ANTENNADIFFAREA 1.687500 ;
    END Y
    PIN Vdd
        DIRECTION INPUT ;
        USE POWER ;
        PORT
        LAYER li ;
        RECT 2.400000 4.500000 2.700000 4.800000 ;
        END
        ANTENNADIFFAREA 0.843750 ;
    END Vdd
    PIN GND
        DIRECTION INPUT ;
        USE GROUND ;
        PORT
        LAYER li ;
        RECT 3.000000 4.500000 3.300000 4.800000 ;
        END
        ANTENNADIFFAREA 0.843750 ;
    END GND
    OBS
      LAYER li ;
         RECT 0.600000 1.800000 2.925000 3.225000 ;
    END
END _0_0std_0_0cells_0_0sky130_fd_sc_hd__nand3_2

MACRO _0_0cell_0_0gcelem3x0
    CLASS CORE ;
    FOREIGN _0_0cell_0_0gcelem3x0 0.000000 0.000000 ;
    ORIGIN 0.000000 0.000000 ;
    SIZE 6.600000 BY 4.200000 ;
    SYMMETRY X Y ;
    SITE CoreSite ;
    PIN in_50_6
        DIRECTION INPUT ;
        USE SIGNAL ;
        PORT
        LAYER li ;
        RECT 0.600000 3.600000 0.900000 3.900000 ;
        END
    END in_50_6
    PIN in_51_6
        DIRECTION INPUT ;
        USE SIGNAL ;
        PORT
        LAYER li ;
        RECT 1.800000 3.600000 2.100000 3.900000 ;
        END
    END in_51_6
    PIN in_52_6
        DIRECTION INPUT ;
        USE SIGNAL ;
        PORT
        LAYER li ;
        RECT 3.000000 3.600000 3.300000 3.900000 ;
        END
    END in_52_6
    PIN out
        DIRECTION OUTPUT ;
        USE SIGNAL ;
        PORT
        LAYER li ;
        RECT 0.600000 0.300000 0.900000 0.600000 ;
        END
        ANTENNADIFFAREA 0.202500 ;
    END out
    PIN Vdd
        DIRECTION INPUT ;
        USE POWER ;
        PORT
        LAYER li ;
        RECT 4.200000 3.600000 4.500000 3.900000 ;
        END
        ANTENNADIFFAREA 0.573750 ;
    END Vdd
    PIN GND
        DIRECTION INPUT ;
        USE GROUND ;
        PORT
        LAYER li ;
        RECT 5.400000 3.600000 5.700000 3.900000 ;
        END
        ANTENNADIFFAREA 0.506250 ;
    END GND
    OBS
      LAYER li ;
         RECT 0.600000 1.800000 5.925000 2.325000 ;
    END
END _0_0cell_0_0gcelem3x0

MACRO _0_0std_0_0cells_0_0TIEHIX1
    CLASS CORE ;
    FOREIGN _0_0std_0_0cells_0_0TIEHIX1 0.000000 0.000000 ;
    ORIGIN 0.000000 0.000000 ;
    SIZE 2.400000 BY 3.000000 ;
    SYMMETRY X Y ;
    SITE CoreSite ;
    PIN Y
        DIRECTION OUTPUT ;
        USE SIGNAL ;
        PORT
        LAYER li ;
        RECT 0.600000 0.300000 0.900000 0.600000 ;
        END
        ANTENNADIFFAREA 0.281250 ;
    END Y
    PIN Vdd
        DIRECTION INPUT ;
        USE POWER ;
        PORT
        LAYER li ;
        RECT 0.600000 2.400000 0.900000 2.700000 ;
        END
        ANTENNADIFFAREA 0.281250 ;
    END Vdd
    PIN GND
        DIRECTION INPUT ;
        USE GROUND ;
        PORT
        LAYER li ;
        RECT 1.800000 2.400000 2.100000 2.700000 ;
        END
        ANTENNADIFFAREA 0.168750 ;
    END GND
END _0_0std_0_0cells_0_0TIEHIX1

MACRO _0_0cell_0_0gnor2x0
    CLASS CORE ;
    FOREIGN _0_0cell_0_0gnor2x0 0.000000 0.000000 ;
    ORIGIN 0.000000 0.000000 ;
    SIZE 3.000000 BY 3.000000 ;
    SYMMETRY X Y ;
    SITE CoreSite ;
    PIN in_50_6
        DIRECTION INPUT ;
        USE SIGNAL ;
        PORT
        LAYER li ;
        RECT 0.600000 2.400000 0.900000 2.700000 ;
        END
    END in_50_6
    PIN in_51_6
        DIRECTION INPUT ;
        USE SIGNAL ;
        PORT
        LAYER li ;
        RECT 1.200000 2.400000 1.500000 2.700000 ;
        END
    END in_51_6
    PIN out
        DIRECTION OUTPUT ;
        USE SIGNAL ;
        PORT
        LAYER li ;
        RECT 0.600000 0.300000 0.900000 0.600000 ;
        END
        ANTENNADIFFAREA 0.506250 ;
    END out
    PIN Vdd
        DIRECTION INPUT ;
        USE POWER ;
        PORT
        LAYER li ;
        RECT 1.800000 2.400000 2.100000 2.700000 ;
        END
        ANTENNADIFFAREA 0.337500 ;
    END Vdd
    PIN GND
        DIRECTION INPUT ;
        USE GROUND ;
        PORT
        LAYER li ;
        RECT 2.400000 2.400000 2.700000 2.700000 ;
        END
        ANTENNADIFFAREA 0.337500 ;
    END GND
END _0_0cell_0_0gnor2x0

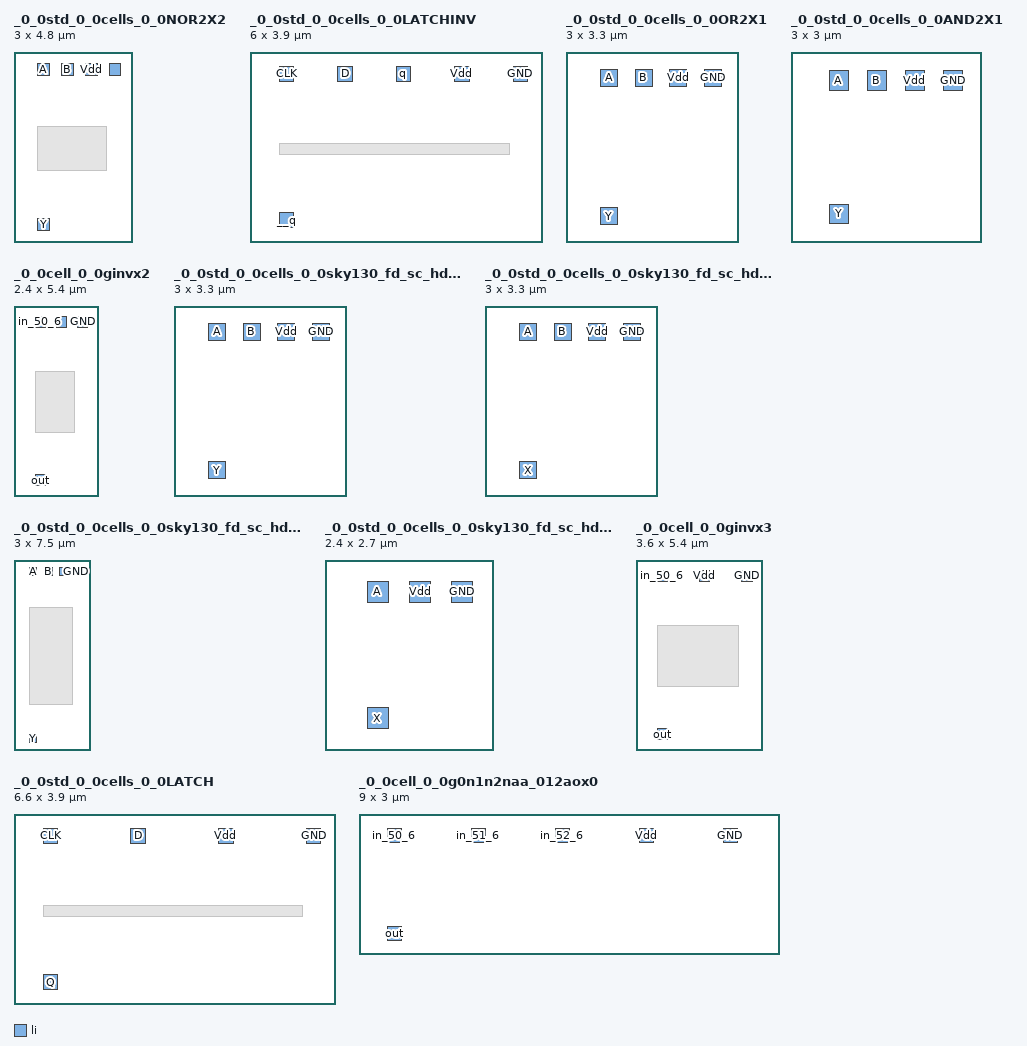
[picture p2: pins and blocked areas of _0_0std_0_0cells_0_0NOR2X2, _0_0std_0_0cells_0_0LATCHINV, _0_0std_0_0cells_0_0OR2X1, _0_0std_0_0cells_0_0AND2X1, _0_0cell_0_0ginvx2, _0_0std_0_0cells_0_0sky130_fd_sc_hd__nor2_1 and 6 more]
MACRO _0_0std_0_0cells_0_0NOR2X2
    CLASS CORE ;
    FOREIGN _0_0std_0_0cells_0_0NOR2X2 0.000000 0.000000 ;
    ORIGIN 0.000000 0.000000 ;
    SIZE 3.000000 BY 4.800000 ;
    SYMMETRY X Y ;
    SITE CoreSite ;
    PIN A
        DIRECTION INPUT ;
        USE SIGNAL ;
        PORT
        LAYER li ;
        RECT 0.600000 4.200000 0.900000 4.500000 ;
        END
    END A
    PIN B
        DIRECTION INPUT ;
        USE SIGNAL ;
        PORT
        LAYER li ;
        RECT 1.200000 4.200000 1.500000 4.500000 ;
        END
    END B
    PIN Y
        DIRECTION OUTPUT ;
        USE SIGNAL ;
        PORT
        LAYER li ;
        RECT 0.600000 0.300000 0.900000 0.600000 ;
        END
        ANTENNADIFFAREA 1.125000 ;
    END Y
    PIN Vdd
        DIRECTION INPUT ;
        USE POWER ;
        PORT
        LAYER li ;
        RECT 1.800000 4.200000 2.100000 4.500000 ;
        END
        ANTENNADIFFAREA 0.843750 ;
    END Vdd
    PIN GND
        DIRECTION INPUT ;
        USE GROUND ;
        PORT
        LAYER li ;
        RECT 2.400000 4.200000 2.700000 4.500000 ;
        END
        ANTENNADIFFAREA 0.562500 ;
    END GND
    OBS
      LAYER li ;
         RECT 0.600000 1.800000 2.325000 2.925000 ;
    END
END _0_0std_0_0cells_0_0NOR2X2

MACRO _0_0std_0_0cells_0_0LATCHINV
    CLASS CORE ;
    FOREIGN _0_0std_0_0cells_0_0LATCHINV 0.000000 0.000000 ;
    ORIGIN 0.000000 0.000000 ;
    SIZE 6.000000 BY 3.900000 ;
    SYMMETRY X Y ;
    SITE CoreSite ;
    PIN CLK
        DIRECTION INPUT ;
        USE SIGNAL ;
        PORT
        LAYER li ;
        RECT 0.600000 3.300000 0.900000 3.600000 ;
        END
    END CLK
    PIN D
        DIRECTION INPUT ;
        USE SIGNAL ;
        PORT
        LAYER li ;
        RECT 1.800000 3.300000 2.100000 3.600000 ;
        END
    END D
    PIN q
        DIRECTION INPUT ;
        USE SIGNAL ;
        PORT
        LAYER li ;
        RECT 3.000000 3.300000 3.300000 3.600000 ;
        END
    END q
    PIN __q
        DIRECTION OUTPUT ;
        USE SIGNAL ;
        PORT
        LAYER li ;
        RECT 0.600000 0.300000 0.900000 0.600000 ;
        END
        ANTENNADIFFAREA 1.406250 ;
    END __q
    PIN Vdd
        DIRECTION INPUT ;
        USE POWER ;
        PORT
        LAYER li ;
        RECT 4.200000 3.300000 4.500000 3.600000 ;
        END
        ANTENNADIFFAREA 0.731250 ;
    END Vdd
    PIN GND
        DIRECTION INPUT ;
        USE GROUND ;
        PORT
        LAYER li ;
        RECT 5.400000 3.300000 5.700000 3.600000 ;
        END
        ANTENNADIFFAREA 0.562500 ;
    END GND
    OBS
      LAYER li ;
         RECT 0.600000 1.800000 5.325000 2.025000 ;
    END
END _0_0std_0_0cells_0_0LATCHINV

MACRO _0_0std_0_0cells_0_0OR2X1
    CLASS CORE ;
    FOREIGN _0_0std_0_0cells_0_0OR2X1 0.000000 0.000000 ;
    ORIGIN 0.000000 0.000000 ;
    SIZE 3.000000 BY 3.300000 ;
    SYMMETRY X Y ;
    SITE CoreSite ;
    PIN A
        DIRECTION INPUT ;
        USE SIGNAL ;
        PORT
        LAYER li ;
        RECT 0.600000 2.700000 0.900000 3.000000 ;
        END
    END A
    PIN B
        DIRECTION INPUT ;
        USE SIGNAL ;
        PORT
        LAYER li ;
        RECT 1.200000 2.700000 1.500000 3.000000 ;
        END
    END B
    PIN Y
        DIRECTION OUTPUT ;
        USE SIGNAL ;
        PORT
        LAYER li ;
        RECT 0.600000 0.300000 0.900000 0.600000 ;
        END
        ANTENNADIFFAREA 0.393750 ;
    END Y
    PIN Vdd
        DIRECTION INPUT ;
        USE POWER ;
        PORT
        LAYER li ;
        RECT 1.800000 2.700000 2.100000 3.000000 ;
        END
        ANTENNADIFFAREA 0.337500 ;
    END Vdd
    PIN GND
        DIRECTION INPUT ;
        USE GROUND ;
        PORT
        LAYER li ;
        RECT 2.400000 2.700000 2.700000 3.000000 ;
        END
        ANTENNADIFFAREA 0.337500 ;
    END GND
END _0_0std_0_0cells_0_0OR2X1

MACRO _0_0std_0_0cells_0_0AND2X1
    CLASS CORE ;
    FOREIGN _0_0std_0_0cells_0_0AND2X1 0.000000 0.000000 ;
    ORIGIN 0.000000 0.000000 ;
    SIZE 3.000000 BY 3.000000 ;
    SYMMETRY X Y ;
    SITE CoreSite ;
    PIN A
        DIRECTION INPUT ;
        USE SIGNAL ;
        PORT
        LAYER li ;
        RECT 0.600000 2.400000 0.900000 2.700000 ;
        END
    END A
    PIN B
        DIRECTION INPUT ;
        USE SIGNAL ;
        PORT
        LAYER li ;
        RECT 1.200000 2.400000 1.500000 2.700000 ;
        END
    END B
    PIN Y
        DIRECTION OUTPUT ;
        USE SIGNAL ;
        PORT
        LAYER li ;
        RECT 0.600000 0.300000 0.900000 0.600000 ;
        END
        ANTENNADIFFAREA 0.393750 ;
    END Y
    PIN Vdd
        DIRECTION INPUT ;
        USE POWER ;
        PORT
        LAYER li ;
        RECT 1.800000 2.400000 2.100000 2.700000 ;
        END
        ANTENNADIFFAREA 0.450000 ;
    END Vdd
    PIN GND
        DIRECTION INPUT ;
        USE GROUND ;
        PORT
        LAYER li ;
        RECT 2.400000 2.400000 2.700000 2.700000 ;
        END
        ANTENNADIFFAREA 0.225000 ;
    END GND
END _0_0std_0_0cells_0_0AND2X1

MACRO _0_0cell_0_0ginvx2
    CLASS CORE ;
    FOREIGN _0_0cell_0_0ginvx2 0.000000 0.000000 ;
    ORIGIN 0.000000 0.000000 ;
    SIZE 2.400000 BY 5.400000 ;
    SYMMETRY X Y ;
    SITE CoreSite ;
    PIN in_50_6
        DIRECTION INPUT ;
        USE SIGNAL ;
        PORT
        LAYER li ;
        RECT 0.600000 4.800000 0.900000 5.100000 ;
        END
    END in_50_6
    PIN out
        DIRECTION OUTPUT ;
        USE SIGNAL ;
        PORT
        LAYER li ;
        RECT 0.600000 0.300000 0.900000 0.600000 ;
        END
        ANTENNADIFFAREA 1.406250 ;
    END out
    PIN Vdd
        DIRECTION INPUT ;
        USE POWER ;
        PORT
        LAYER li ;
        RECT 1.200000 4.800000 1.500000 5.100000 ;
        END
        ANTENNADIFFAREA 0.843750 ;
    END Vdd
    PIN GND
        DIRECTION INPUT ;
        USE GROUND ;
        PORT
        LAYER li ;
        RECT 1.800000 4.800000 2.100000 5.100000 ;
        END
        ANTENNADIFFAREA 0.562500 ;
    END GND
    OBS
      LAYER li ;
         RECT 0.600000 1.800000 1.725000 3.525000 ;
    END
END _0_0cell_0_0ginvx2

MACRO _0_0std_0_0cells_0_0sky130_fd_sc_hd__nor2_1
    CLASS CORE ;
    FOREIGN _0_0std_0_0cells_0_0sky130_fd_sc_hd__nor2_1 0.000000 0.000000 ;
    ORIGIN 0.000000 0.000000 ;
    SIZE 3.000000 BY 3.300000 ;
    SYMMETRY X Y ;
    SITE CoreSite ;
    PIN A
        DIRECTION INPUT ;
        USE SIGNAL ;
        PORT
        LAYER li ;
        RECT 0.600000 2.700000 0.900000 3.000000 ;
        END
    END A
    PIN B
        DIRECTION INPUT ;
        USE SIGNAL ;
        PORT
        LAYER li ;
        RECT 1.200000 2.700000 1.500000 3.000000 ;
        END
    END B
    PIN Y
        DIRECTION OUTPUT ;
        USE SIGNAL ;
        PORT
        LAYER li ;
        RECT 0.600000 0.300000 0.900000 0.600000 ;
        END
        ANTENNADIFFAREA 0.590625 ;
    END Y
    PIN Vdd
        DIRECTION INPUT ;
        USE POWER ;
        PORT
        LAYER li ;
        RECT 1.800000 2.700000 2.100000 3.000000 ;
        END
        ANTENNADIFFAREA 0.421875 ;
    END Vdd
    PIN GND
        DIRECTION INPUT ;
        USE GROUND ;
        PORT
        LAYER li ;
        RECT 2.400000 2.700000 2.700000 3.000000 ;
        END
        ANTENNADIFFAREA 0.337500 ;
    END GND
END _0_0std_0_0cells_0_0sky130_fd_sc_hd__nor2_1

MACRO _0_0std_0_0cells_0_0sky130_fd_sc_hd__or2_0
    CLASS CORE ;
    FOREIGN _0_0std_0_0cells_0_0sky130_fd_sc_hd__or2_0 0.000000 0.000000 ;
    ORIGIN 0.000000 0.000000 ;
    SIZE 3.000000 BY 3.300000 ;
    SYMMETRY X Y ;
    SITE CoreSite ;
    PIN A
        DIRECTION INPUT ;
        USE SIGNAL ;
        PORT
        LAYER li ;
        RECT 0.600000 2.700000 0.900000 3.000000 ;
        END
    END A
    PIN B
        DIRECTION INPUT ;
        USE SIGNAL ;
        PORT
        LAYER li ;
        RECT 1.200000 2.700000 1.500000 3.000000 ;
        END
    END B
    PIN X
        DIRECTION OUTPUT ;
        USE SIGNAL ;
        PORT
        LAYER li ;
        RECT 0.600000 0.300000 0.900000 0.600000 ;
        END
        ANTENNADIFFAREA 0.393750 ;
    END X
    PIN Vdd
        DIRECTION INPUT ;
        USE POWER ;
        PORT
        LAYER li ;
        RECT 1.800000 2.700000 2.100000 3.000000 ;
        END
        ANTENNADIFFAREA 0.337500 ;
    END Vdd
    PIN GND
        DIRECTION INPUT ;
        USE GROUND ;
        PORT
        LAYER li ;
        RECT 2.400000 2.700000 2.700000 3.000000 ;
        END
        ANTENNADIFFAREA 0.337500 ;
    END GND
END _0_0std_0_0cells_0_0sky130_fd_sc_hd__or2_0

MACRO _0_0std_0_0cells_0_0sky130_fd_sc_hd__nor2_4
    CLASS CORE ;
    FOREIGN _0_0std_0_0cells_0_0sky130_fd_sc_hd__nor2_4 0.000000 0.000000 ;
    ORIGIN 0.000000 0.000000 ;
    SIZE 3.000000 BY 7.500000 ;
    SYMMETRY X Y ;
    SITE CoreSite ;
    PIN A
        DIRECTION INPUT ;
        USE SIGNAL ;
        PORT
        LAYER li ;
        RECT 0.600000 6.900000 0.900000 7.200000 ;
        END
    END A
    PIN B
        DIRECTION INPUT ;
        USE SIGNAL ;
        PORT
        LAYER li ;
        RECT 1.200000 6.900000 1.500000 7.200000 ;
        END
    END B
    PIN Y
        DIRECTION OUTPUT ;
        USE SIGNAL ;
        PORT
        LAYER li ;
        RECT 0.600000 0.300000 0.900000 0.600000 ;
        END
        ANTENNADIFFAREA 2.250000 ;
    END Y
    PIN Vdd
        DIRECTION INPUT ;
        USE POWER ;
        PORT
        LAYER li ;
        RECT 1.800000 6.900000 2.100000 7.200000 ;
        END
        ANTENNADIFFAREA 1.687500 ;
    END Vdd
    PIN GND
        DIRECTION INPUT ;
        USE GROUND ;
        PORT
        LAYER li ;
        RECT 2.400000 6.900000 2.700000 7.200000 ;
        END
        ANTENNADIFFAREA 1.125000 ;
    END GND
    OBS
      LAYER li ;
         RECT 0.600000 1.800000 2.325000 5.625000 ;
    END
END _0_0std_0_0cells_0_0sky130_fd_sc_hd__nor2_4

MACRO _0_0std_0_0cells_0_0sky130_fd_sc_hd__clkbuf_1
    CLASS CORE ;
    FOREIGN _0_0std_0_0cells_0_0sky130_fd_sc_hd__clkbuf_1 0.000000 0.000000 ;
    ORIGIN 0.000000 0.000000 ;
    SIZE 2.400000 BY 2.700000 ;
    SYMMETRY X Y ;
    SITE CoreSite ;
    PIN A
        DIRECTION INPUT ;
        USE SIGNAL ;
        PORT
        LAYER li ;
        RECT 0.600000 2.100000 0.900000 2.400000 ;
        END
    END A
    PIN X
        DIRECTION OUTPUT ;
        USE SIGNAL ;
        PORT
        LAYER li ;
        RECT 0.600000 0.300000 0.900000 0.600000 ;
        END
        ANTENNADIFFAREA 0.393750 ;
    END X
    PIN Vdd
        DIRECTION INPUT ;
        USE POWER ;
        PORT
        LAYER li ;
        RECT 1.200000 2.100000 1.500000 2.400000 ;
        END
        ANTENNADIFFAREA 0.225000 ;
    END Vdd
    PIN GND
        DIRECTION INPUT ;
        USE GROUND ;
        PORT
        LAYER li ;
        RECT 1.800000 2.100000 2.100000 2.400000 ;
        END
        ANTENNADIFFAREA 0.168750 ;
    END GND
END _0_0std_0_0cells_0_0sky130_fd_sc_hd__clkbuf_1

MACRO _0_0cell_0_0ginvx3
    CLASS CORE ;
    FOREIGN _0_0cell_0_0ginvx3 0.000000 0.000000 ;
    ORIGIN 0.000000 0.000000 ;
    SIZE 3.600000 BY 5.400000 ;
    SYMMETRY X Y ;
    SITE CoreSite ;
    PIN in_50_6
        DIRECTION INPUT ;
        USE SIGNAL ;
        PORT
        LAYER li ;
        RECT 0.600000 4.800000 0.900000 5.100000 ;
        END
    END in_50_6
    PIN out
        DIRECTION OUTPUT ;
        USE SIGNAL ;
        PORT
        LAYER li ;
        RECT 0.600000 0.300000 0.900000 0.600000 ;
        END
        ANTENNADIFFAREA 3.375000 ;
    END out
    PIN Vdd
        DIRECTION INPUT ;
        USE POWER ;
        PORT
        LAYER li ;
        RECT 1.800000 4.800000 2.100000 5.100000 ;
        END
        ANTENNADIFFAREA 2.531250 ;
    END Vdd
    PIN GND
        DIRECTION INPUT ;
        USE GROUND ;
        PORT
        LAYER li ;
        RECT 3.000000 4.800000 3.300000 5.100000 ;
        END
        ANTENNADIFFAREA 1.125000 ;
    END GND
    OBS
      LAYER li ;
         RECT 0.600000 1.800000 2.925000 3.525000 ;
    END
END _0_0cell_0_0ginvx3

MACRO _0_0std_0_0cells_0_0LATCH
    CLASS CORE ;
    FOREIGN _0_0std_0_0cells_0_0LATCH 0.000000 0.000000 ;
    ORIGIN 0.000000 0.000000 ;
    SIZE 6.600000 BY 3.900000 ;
    SYMMETRY X Y ;
    SITE CoreSite ;
    PIN CLK
        DIRECTION INPUT ;
        USE SIGNAL ;
        PORT
        LAYER li ;
        RECT 0.600000 3.300000 0.900000 3.600000 ;
        END
    END CLK
    PIN D
        DIRECTION INPUT ;
        USE SIGNAL ;
        PORT
        LAYER li ;
        RECT 2.400000 3.300000 2.700000 3.600000 ;
        END
    END D
    PIN Q
        DIRECTION OUTPUT ;
        USE SIGNAL ;
        PORT
        LAYER li ;
        RECT 0.600000 0.300000 0.900000 0.600000 ;
        END
        ANTENNADIFFAREA 0.703125 ;
    END Q
    PIN Vdd
        DIRECTION INPUT ;
        USE POWER ;
        PORT
        LAYER li ;
        RECT 4.200000 3.300000 4.500000 3.600000 ;
        END
        ANTENNADIFFAREA 0.590625 ;
    END Vdd
    PIN GND
        DIRECTION INPUT ;
        USE GROUND ;
        PORT
        LAYER li ;
        RECT 6.000000 3.300000 6.300000 3.600000 ;
        END
        ANTENNADIFFAREA 0.675000 ;
    END GND
    OBS
      LAYER li ;
         RECT 0.600000 1.800000 5.925000 2.025000 ;
    END
END _0_0std_0_0cells_0_0LATCH

MACRO _0_0cell_0_0g0n1n2naa_012aox0
    CLASS CORE ;
    FOREIGN _0_0cell_0_0g0n1n2naa_012aox0 0.000000 0.000000 ;
    ORIGIN 0.000000 0.000000 ;
    SIZE 9.000000 BY 3.000000 ;
    SYMMETRY X Y ;
    SITE CoreSite ;
    PIN in_50_6
        DIRECTION INPUT ;
        USE SIGNAL ;
        PORT
        LAYER li ;
        RECT 0.600000 2.400000 0.900000 2.700000 ;
        END
    END in_50_6
    PIN in_51_6
        DIRECTION INPUT ;
        USE SIGNAL ;
        PORT
        LAYER li ;
        RECT 2.400000 2.400000 2.700000 2.700000 ;
        END
    END in_51_6
    PIN in_52_6
        DIRECTION INPUT ;
        USE SIGNAL ;
        PORT
        LAYER li ;
        RECT 4.200000 2.400000 4.500000 2.700000 ;
        END
    END in_52_6
    PIN out
        DIRECTION OUTPUT ;
        USE SIGNAL ;
        PORT
        LAYER li ;
        RECT 0.600000 0.300000 0.900000 0.600000 ;
        END
        ANTENNADIFFAREA 0.506250 ;
    END out
    PIN Vdd
        DIRECTION INPUT ;
        USE POWER ;
        PORT
        LAYER li ;
        RECT 6.000000 2.400000 6.300000 2.700000 ;
        END
        ANTENNADIFFAREA 0.731250 ;
    END Vdd
    PIN GND
        DIRECTION INPUT ;
        USE GROUND ;
        PORT
        LAYER li ;
        RECT 7.800000 2.400000 8.100000 2.700000 ;
        END
        ANTENNADIFFAREA 0.506250 ;
    END GND
END _0_0cell_0_0g0n1n2naa_012aox0

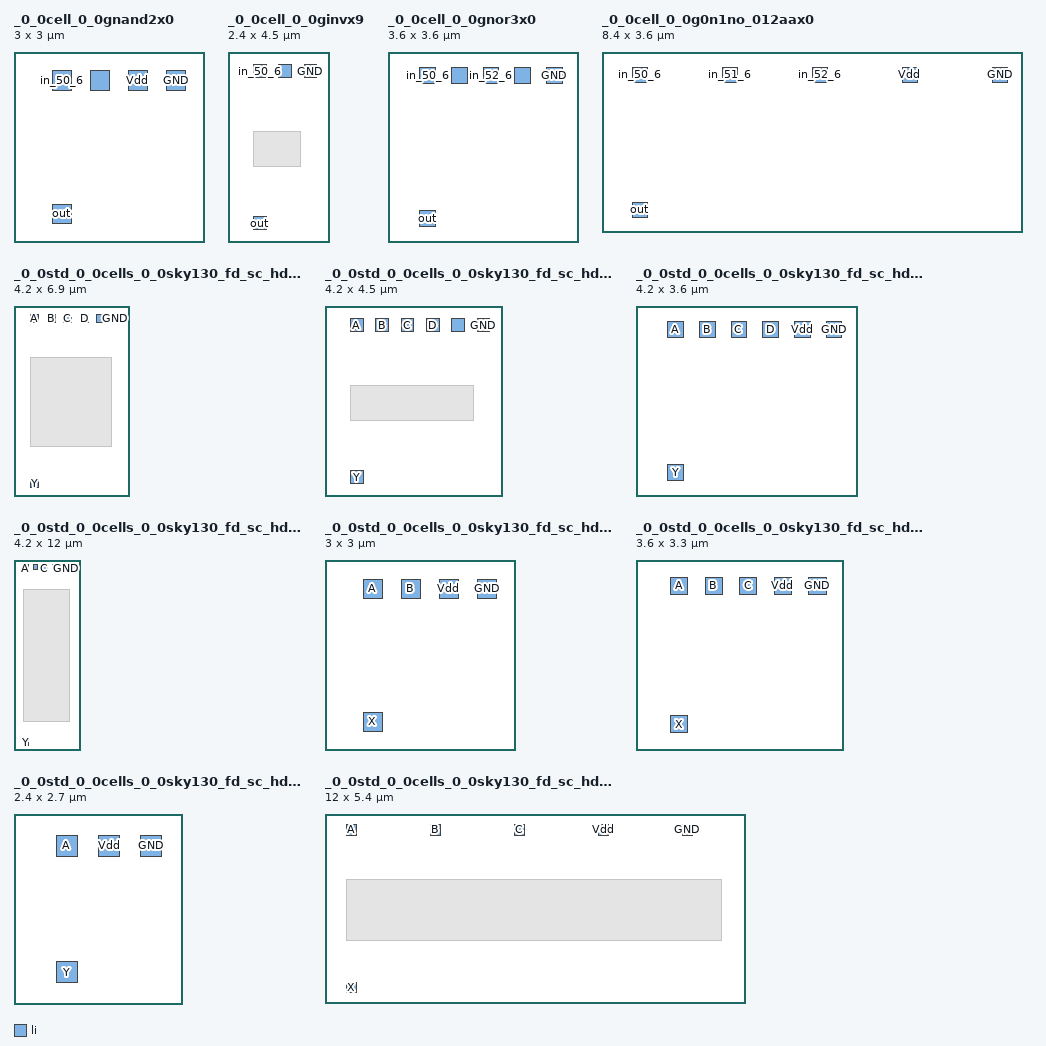
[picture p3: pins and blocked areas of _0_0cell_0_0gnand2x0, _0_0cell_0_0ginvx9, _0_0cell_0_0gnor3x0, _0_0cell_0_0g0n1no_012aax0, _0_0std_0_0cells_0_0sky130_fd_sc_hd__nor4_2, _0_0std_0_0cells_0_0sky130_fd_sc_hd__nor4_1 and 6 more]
MACRO _0_0cell_0_0gnand2x0
    CLASS CORE ;
    FOREIGN _0_0cell_0_0gnand2x0 0.000000 0.000000 ;
    ORIGIN 0.000000 0.000000 ;
    SIZE 3.000000 BY 3.000000 ;
    SYMMETRY X Y ;
    SITE CoreSite ;
    PIN in_50_6
        DIRECTION INPUT ;
        USE SIGNAL ;
        PORT
        LAYER li ;
        RECT 0.600000 2.400000 0.900000 2.700000 ;
        END
    END in_50_6
    PIN in_51_6
        DIRECTION INPUT ;
        USE SIGNAL ;
        PORT
        LAYER li ;
        RECT 1.200000 2.400000 1.500000 2.700000 ;
        END
    END in_51_6
    PIN out
        DIRECTION OUTPUT ;
        USE SIGNAL ;
        PORT
        LAYER li ;
        RECT 0.600000 0.300000 0.900000 0.600000 ;
        END
        ANTENNADIFFAREA 0.450000 ;
    END out
    PIN Vdd
        DIRECTION INPUT ;
        USE POWER ;
        PORT
        LAYER li ;
        RECT 1.800000 2.400000 2.100000 2.700000 ;
        END
        ANTENNADIFFAREA 0.337500 ;
    END Vdd
    PIN GND
        DIRECTION INPUT ;
        USE GROUND ;
        PORT
        LAYER li ;
        RECT 2.400000 2.400000 2.700000 2.700000 ;
        END
        ANTENNADIFFAREA 0.281250 ;
    END GND
END _0_0cell_0_0gnand2x0

MACRO _0_0cell_0_0ginvx9
    CLASS CORE ;
    FOREIGN _0_0cell_0_0ginvx9 0.000000 0.000000 ;
    ORIGIN 0.000000 0.000000 ;
    SIZE 2.400000 BY 4.500000 ;
    SYMMETRY X Y ;
    SITE CoreSite ;
    PIN in_50_6
        DIRECTION INPUT ;
        USE SIGNAL ;
        PORT
        LAYER li ;
        RECT 0.600000 3.900000 0.900000 4.200000 ;
        END
    END in_50_6
    PIN out
        DIRECTION OUTPUT ;
        USE SIGNAL ;
        PORT
        LAYER li ;
        RECT 0.600000 0.300000 0.900000 0.600000 ;
        END
        ANTENNADIFFAREA 1.462500 ;
    END out
    PIN Vdd
        DIRECTION INPUT ;
        USE POWER ;
        PORT
        LAYER li ;
        RECT 1.200000 3.900000 1.500000 4.200000 ;
        END
        ANTENNADIFFAREA 1.237500 ;
    END Vdd
    PIN GND
        DIRECTION INPUT ;
        USE GROUND ;
        PORT
        LAYER li ;
        RECT 1.800000 3.900000 2.100000 4.200000 ;
        END
        ANTENNADIFFAREA 0.421875 ;
    END GND
    OBS
      LAYER li ;
         RECT 0.600000 1.800000 1.725000 2.625000 ;
    END
END _0_0cell_0_0ginvx9

MACRO _0_0cell_0_0gnor3x0
    CLASS CORE ;
    FOREIGN _0_0cell_0_0gnor3x0 0.000000 0.000000 ;
    ORIGIN 0.000000 0.000000 ;
    SIZE 3.600000 BY 3.600000 ;
    SYMMETRY X Y ;
    SITE CoreSite ;
    PIN in_50_6
        DIRECTION INPUT ;
        USE SIGNAL ;
        PORT
        LAYER li ;
        RECT 0.600000 3.000000 0.900000 3.300000 ;
        END
    END in_50_6
    PIN in_51_6
        DIRECTION INPUT ;
        USE SIGNAL ;
        PORT
        LAYER li ;
        RECT 1.200000 3.000000 1.500000 3.300000 ;
        END
    END in_51_6
    PIN in_52_6
        DIRECTION INPUT ;
        USE SIGNAL ;
        PORT
        LAYER li ;
        RECT 1.800000 3.000000 2.100000 3.300000 ;
        END
    END in_52_6
    PIN out
        DIRECTION OUTPUT ;
        USE SIGNAL ;
        PORT
        LAYER li ;
        RECT 0.600000 0.300000 0.900000 0.600000 ;
        END
        ANTENNADIFFAREA 0.843750 ;
    END out
    PIN Vdd
        DIRECTION INPUT ;
        USE POWER ;
        PORT
        LAYER li ;
        RECT 2.400000 3.000000 2.700000 3.300000 ;
        END
        ANTENNADIFFAREA 0.506250 ;
    END Vdd
    PIN GND
        DIRECTION INPUT ;
        USE GROUND ;
        PORT
        LAYER li ;
        RECT 3.000000 3.000000 3.300000 3.300000 ;
        END
        ANTENNADIFFAREA 0.337500 ;
    END GND
END _0_0cell_0_0gnor3x0

MACRO _0_0cell_0_0g0n1no_012aax0
    CLASS CORE ;
    FOREIGN _0_0cell_0_0g0n1no_012aax0 0.000000 0.000000 ;
    ORIGIN 0.000000 0.000000 ;
    SIZE 8.400000 BY 3.600000 ;
    SYMMETRY X Y ;
    SITE CoreSite ;
    PIN in_50_6
        DIRECTION INPUT ;
        USE SIGNAL ;
        PORT
        LAYER li ;
        RECT 0.600000 3.000000 0.900000 3.300000 ;
        END
    END in_50_6
    PIN in_51_6
        DIRECTION INPUT ;
        USE SIGNAL ;
        PORT
        LAYER li ;
        RECT 2.400000 3.000000 2.700000 3.300000 ;
        END
    END in_51_6
    PIN in_52_6
        DIRECTION INPUT ;
        USE SIGNAL ;
        PORT
        LAYER li ;
        RECT 4.200000 3.000000 4.500000 3.300000 ;
        END
    END in_52_6
    PIN out
        DIRECTION OUTPUT ;
        USE SIGNAL ;
        PORT
        LAYER li ;
        RECT 0.600000 0.300000 0.900000 0.600000 ;
        END
        ANTENNADIFFAREA 0.928125 ;
    END out
    PIN Vdd
        DIRECTION INPUT ;
        USE POWER ;
        PORT
        LAYER li ;
        RECT 6.000000 3.000000 6.300000 3.300000 ;
        END
        ANTENNADIFFAREA 0.270000 ;
    END Vdd
    PIN GND
        DIRECTION INPUT ;
        USE GROUND ;
        PORT
        LAYER li ;
        RECT 7.800000 3.000000 8.100000 3.300000 ;
        END
        ANTENNADIFFAREA 0.506250 ;
    END GND
END _0_0cell_0_0g0n1no_012aax0

MACRO _0_0std_0_0cells_0_0sky130_fd_sc_hd__nor4_2
    CLASS CORE ;
    FOREIGN _0_0std_0_0cells_0_0sky130_fd_sc_hd__nor4_2 0.000000 0.000000 ;
    ORIGIN 0.000000 0.000000 ;
    SIZE 4.200000 BY 6.900000 ;
    SYMMETRY X Y ;
    SITE CoreSite ;
    PIN A
        DIRECTION INPUT ;
        USE SIGNAL ;
        PORT
        LAYER li ;
        RECT 0.600000 6.300000 0.900000 6.600000 ;
        END
    END A
    PIN B
        DIRECTION INPUT ;
        USE SIGNAL ;
        PORT
        LAYER li ;
        RECT 1.200000 6.300000 1.500000 6.600000 ;
        END
    END B
    PIN C
        DIRECTION INPUT ;
        USE SIGNAL ;
        PORT
        LAYER li ;
        RECT 1.800000 6.300000 2.100000 6.600000 ;
        END
    END C
    PIN D
        DIRECTION INPUT ;
        USE SIGNAL ;
        PORT
        LAYER li ;
        RECT 2.400000 6.300000 2.700000 6.600000 ;
        END
    END D
    PIN Y
        DIRECTION OUTPUT ;
        USE SIGNAL ;
        PORT
        LAYER li ;
        RECT 0.600000 0.300000 0.900000 0.600000 ;
        END
        ANTENNADIFFAREA 2.250000 ;
    END Y
    PIN Vdd
        DIRECTION INPUT ;
        USE POWER ;
        PORT
        LAYER li ;
        RECT 3.000000 6.300000 3.300000 6.600000 ;
        END
        ANTENNADIFFAREA 1.687500 ;
    END Vdd
    PIN GND
        DIRECTION INPUT ;
        USE GROUND ;
        PORT
        LAYER li ;
        RECT 3.600000 6.300000 3.900000 6.600000 ;
        END
        ANTENNADIFFAREA 0.843750 ;
    END GND
    OBS
      LAYER li ;
         RECT 0.600000 1.800000 3.525000 5.025000 ;
    END
END _0_0std_0_0cells_0_0sky130_fd_sc_hd__nor4_2

MACRO _0_0std_0_0cells_0_0sky130_fd_sc_hd__nor4_1
    CLASS CORE ;
    FOREIGN _0_0std_0_0cells_0_0sky130_fd_sc_hd__nor4_1 0.000000 0.000000 ;
    ORIGIN 0.000000 0.000000 ;
    SIZE 4.200000 BY 4.500000 ;
    SYMMETRY X Y ;
    SITE CoreSite ;
    PIN A
        DIRECTION INPUT ;
        USE SIGNAL ;
        PORT
        LAYER li ;
        RECT 0.600000 3.900000 0.900000 4.200000 ;
        END
    END A
    PIN B
        DIRECTION INPUT ;
        USE SIGNAL ;
        PORT
        LAYER li ;
        RECT 1.200000 3.900000 1.500000 4.200000 ;
        END
    END B
    PIN C
        DIRECTION INPUT ;
        USE SIGNAL ;
        PORT
        LAYER li ;
        RECT 1.800000 3.900000 2.100000 4.200000 ;
        END
    END C
    PIN D
        DIRECTION INPUT ;
        USE SIGNAL ;
        PORT
        LAYER li ;
        RECT 2.400000 3.900000 2.700000 4.200000 ;
        END
    END D
    PIN Y
        DIRECTION OUTPUT ;
        USE SIGNAL ;
        PORT
        LAYER li ;
        RECT 0.600000 0.300000 0.900000 0.600000 ;
        END
        ANTENNADIFFAREA 1.181250 ;
    END Y
    PIN Vdd
        DIRECTION INPUT ;
        USE POWER ;
        PORT
        LAYER li ;
        RECT 3.000000 3.900000 3.300000 4.200000 ;
        END
        ANTENNADIFFAREA 0.843750 ;
    END Vdd
    PIN GND
        DIRECTION INPUT ;
        USE GROUND ;
        PORT
        LAYER li ;
        RECT 3.600000 3.900000 3.900000 4.200000 ;
        END
        ANTENNADIFFAREA 0.506250 ;
    END GND
    OBS
      LAYER li ;
         RECT 0.600000 1.800000 3.525000 2.625000 ;
    END
END _0_0std_0_0cells_0_0sky130_fd_sc_hd__nor4_1

MACRO _0_0std_0_0cells_0_0sky130_fd_sc_hd__nand4_1
    CLASS CORE ;
    FOREIGN _0_0std_0_0cells_0_0sky130_fd_sc_hd__nand4_1 0.000000 0.000000 ;
    ORIGIN 0.000000 0.000000 ;
    SIZE 4.200000 BY 3.600000 ;
    SYMMETRY X Y ;
    SITE CoreSite ;
    PIN A
        DIRECTION INPUT ;
        USE SIGNAL ;
        PORT
        LAYER li ;
        RECT 0.600000 3.000000 0.900000 3.300000 ;
        END
    END A
    PIN B
        DIRECTION INPUT ;
        USE SIGNAL ;
        PORT
        LAYER li ;
        RECT 1.200000 3.000000 1.500000 3.300000 ;
        END
    END B
    PIN C
        DIRECTION INPUT ;
        USE SIGNAL ;
        PORT
        LAYER li ;
        RECT 1.800000 3.000000 2.100000 3.300000 ;
        END
    END C
    PIN D
        DIRECTION INPUT ;
        USE SIGNAL ;
        PORT
        LAYER li ;
        RECT 2.400000 3.000000 2.700000 3.300000 ;
        END
    END D
    PIN Y
        DIRECTION OUTPUT ;
        USE SIGNAL ;
        PORT
        LAYER li ;
        RECT 0.600000 0.300000 0.900000 0.600000 ;
        END
        ANTENNADIFFAREA 1.012500 ;
    END Y
    PIN Vdd
        DIRECTION INPUT ;
        USE POWER ;
        PORT
        LAYER li ;
        RECT 3.000000 3.000000 3.300000 3.300000 ;
        END
        ANTENNADIFFAREA 0.675000 ;
    END Vdd
    PIN GND
        DIRECTION INPUT ;
        USE GROUND ;
        PORT
        LAYER li ;
        RECT 3.600000 3.000000 3.900000 3.300000 ;
        END
        ANTENNADIFFAREA 0.562500 ;
    END GND
END _0_0std_0_0cells_0_0sky130_fd_sc_hd__nand4_1

MACRO _0_0std_0_0cells_0_0sky130_fd_sc_hd__nor4_4
    CLASS CORE ;
    FOREIGN _0_0std_0_0cells_0_0sky130_fd_sc_hd__nor4_4 0.000000 0.000000 ;
    ORIGIN 0.000000 0.000000 ;
    SIZE 4.200000 BY 12.000000 ;
    SYMMETRY X Y ;
    SITE CoreSite ;
    PIN A
        DIRECTION INPUT ;
        USE SIGNAL ;
        PORT
        LAYER li ;
        RECT 0.600000 11.400000 0.900000 11.700000 ;
        END
    END A
    PIN B
        DIRECTION INPUT ;
        USE SIGNAL ;
        PORT
        LAYER li ;
        RECT 1.200000 11.400000 1.500000 11.700000 ;
        END
    END B
    PIN C
        DIRECTION INPUT ;
        USE SIGNAL ;
        PORT
        LAYER li ;
        RECT 1.800000 11.400000 2.100000 11.700000 ;
        END
    END C
    PIN D
        DIRECTION INPUT ;
        USE SIGNAL ;
        PORT
        LAYER li ;
        RECT 2.400000 11.400000 2.700000 11.700000 ;
        END
    END D
    PIN Y
        DIRECTION OUTPUT ;
        USE SIGNAL ;
        PORT
        LAYER li ;
        RECT 0.600000 0.300000 0.900000 0.600000 ;
        END
        ANTENNADIFFAREA 4.528125 ;
    END Y
    PIN Vdd
        DIRECTION INPUT ;
        USE POWER ;
        PORT
        LAYER li ;
        RECT 3.000000 11.400000 3.300000 11.700000 ;
        END
        ANTENNADIFFAREA 3.403125 ;
    END Vdd
    PIN GND
        DIRECTION INPUT ;
        USE GROUND ;
        PORT
        LAYER li ;
        RECT 3.600000 11.400000 3.900000 11.700000 ;
        END
        ANTENNADIFFAREA 1.687500 ;
    END GND
    OBS
      LAYER li ;
         RECT 0.600000 1.800000 3.525000 10.125000 ;
    END
END _0_0std_0_0cells_0_0sky130_fd_sc_hd__nor4_4

MACRO _0_0std_0_0cells_0_0sky130_fd_sc_hd__and2_0
    CLASS CORE ;
    FOREIGN _0_0std_0_0cells_0_0sky130_fd_sc_hd__and2_0 0.000000 0.000000 ;
    ORIGIN 0.000000 0.000000 ;
    SIZE 3.000000 BY 3.000000 ;
    SYMMETRY X Y ;
    SITE CoreSite ;
    PIN A
        DIRECTION INPUT ;
        USE SIGNAL ;
        PORT
        LAYER li ;
        RECT 0.600000 2.400000 0.900000 2.700000 ;
        END
    END A
    PIN B
        DIRECTION INPUT ;
        USE SIGNAL ;
        PORT
        LAYER li ;
        RECT 1.200000 2.400000 1.500000 2.700000 ;
        END
    END B
    PIN X
        DIRECTION OUTPUT ;
        USE SIGNAL ;
        PORT
        LAYER li ;
        RECT 0.600000 0.300000 0.900000 0.600000 ;
        END
        ANTENNADIFFAREA 0.393750 ;
    END X
    PIN Vdd
        DIRECTION INPUT ;
        USE POWER ;
        PORT
        LAYER li ;
        RECT 1.800000 2.400000 2.100000 2.700000 ;
        END
        ANTENNADIFFAREA 0.450000 ;
    END Vdd
    PIN GND
        DIRECTION INPUT ;
        USE GROUND ;
        PORT
        LAYER li ;
        RECT 2.400000 2.400000 2.700000 2.700000 ;
        END
        ANTENNADIFFAREA 0.225000 ;
    END GND
END _0_0std_0_0cells_0_0sky130_fd_sc_hd__and2_0

MACRO _0_0std_0_0cells_0_0sky130_fd_sc_hd__and3_1
    CLASS CORE ;
    FOREIGN _0_0std_0_0cells_0_0sky130_fd_sc_hd__and3_1 0.000000 0.000000 ;
    ORIGIN 0.000000 0.000000 ;
    SIZE 3.600000 BY 3.300000 ;
    SYMMETRY X Y ;
    SITE CoreSite ;
    PIN A
        DIRECTION INPUT ;
        USE SIGNAL ;
        PORT
        LAYER li ;
        RECT 0.600000 2.700000 0.900000 3.000000 ;
        END
    END A
    PIN B
        DIRECTION INPUT ;
        USE SIGNAL ;
        PORT
        LAYER li ;
        RECT 1.200000 2.700000 1.500000 3.000000 ;
        END
    END B
    PIN C
        DIRECTION INPUT ;
        USE SIGNAL ;
        PORT
        LAYER li ;
        RECT 1.800000 2.700000 2.100000 3.000000 ;
        END
    END C
    PIN X
        DIRECTION OUTPUT ;
        USE SIGNAL ;
        PORT
        LAYER li ;
        RECT 0.600000 0.300000 0.900000 0.600000 ;
        END
        ANTENNADIFFAREA 0.393750 ;
    END X
    PIN Vdd
        DIRECTION INPUT ;
        USE POWER ;
        PORT
        LAYER li ;
        RECT 2.400000 2.700000 2.700000 3.000000 ;
        END
        ANTENNADIFFAREA 0.450000 ;
    END Vdd
    PIN GND
        DIRECTION INPUT ;
        USE GROUND ;
        PORT
        LAYER li ;
        RECT 3.000000 2.700000 3.300000 3.000000 ;
        END
        ANTENNADIFFAREA 0.337500 ;
    END GND
END _0_0std_0_0cells_0_0sky130_fd_sc_hd__and3_1

MACRO _0_0std_0_0cells_0_0sky130_fd_sc_hd__clkinv_1
    CLASS CORE ;
    FOREIGN _0_0std_0_0cells_0_0sky130_fd_sc_hd__clkinv_1 0.000000 0.000000 ;
    ORIGIN 0.000000 0.000000 ;
    SIZE 2.400000 BY 2.700000 ;
    SYMMETRY X Y ;
    SITE CoreSite ;
    PIN A
        DIRECTION INPUT ;
        USE SIGNAL ;
        PORT
        LAYER li ;
        RECT 0.600000 2.100000 0.900000 2.400000 ;
        END
    END A
    PIN Y
        DIRECTION OUTPUT ;
        USE SIGNAL ;
        PORT
        LAYER li ;
        RECT 0.600000 0.300000 0.900000 0.600000 ;
        END
        ANTENNADIFFAREA 0.393750 ;
    END Y
    PIN Vdd
        DIRECTION INPUT ;
        USE POWER ;
        PORT
        LAYER li ;
        RECT 1.200000 2.100000 1.500000 2.400000 ;
        END
        ANTENNADIFFAREA 0.225000 ;
    END Vdd
    PIN GND
        DIRECTION INPUT ;
        USE GROUND ;
        PORT
        LAYER li ;
        RECT 1.800000 2.100000 2.100000 2.400000 ;
        END
        ANTENNADIFFAREA 0.168750 ;
    END GND
END _0_0std_0_0cells_0_0sky130_fd_sc_hd__clkinv_1

MACRO _0_0std_0_0cells_0_0sky130_fd_sc_hd__xnor3_2
    CLASS CORE ;
    FOREIGN _0_0std_0_0cells_0_0sky130_fd_sc_hd__xnor3_2 0.000000 0.000000 ;
    ORIGIN 0.000000 0.000000 ;
    SIZE 12.000000 BY 5.400000 ;
    SYMMETRY X Y ;
    SITE CoreSite ;
    PIN A
        DIRECTION INPUT ;
        USE SIGNAL ;
        PORT
        LAYER li ;
        RECT 0.600000 4.800000 0.900000 5.100000 ;
        END
    END A
    PIN B
        DIRECTION INPUT ;
        USE SIGNAL ;
        PORT
        LAYER li ;
        RECT 3.000000 4.800000 3.300000 5.100000 ;
        END
    END B
    PIN C
        DIRECTION INPUT ;
        USE SIGNAL ;
        PORT
        LAYER li ;
        RECT 5.400000 4.800000 5.700000 5.100000 ;
        END
    END C
    PIN X
        DIRECTION OUTPUT ;
        USE SIGNAL ;
        PORT
        LAYER li ;
        RECT 0.600000 0.300000 0.900000 0.600000 ;
        END
        ANTENNADIFFAREA 1.828125 ;
    END X
    PIN Vdd
        DIRECTION INPUT ;
        USE POWER ;
        PORT
        LAYER li ;
        RECT 7.800000 4.800000 8.100000 5.100000 ;
        END
        ANTENNADIFFAREA 0.725625 ;
    END Vdd
    PIN GND
        DIRECTION INPUT ;
        USE GROUND ;
        PORT
        LAYER li ;
        RECT 10.200000 4.800000 10.500000 5.100000 ;
        END
        ANTENNADIFFAREA 1.001250 ;
    END GND
    OBS
      LAYER li ;
         RECT 0.600000 1.800000 11.325000 3.525000 ;
    END
END _0_0std_0_0cells_0_0sky130_fd_sc_hd__xnor3_2

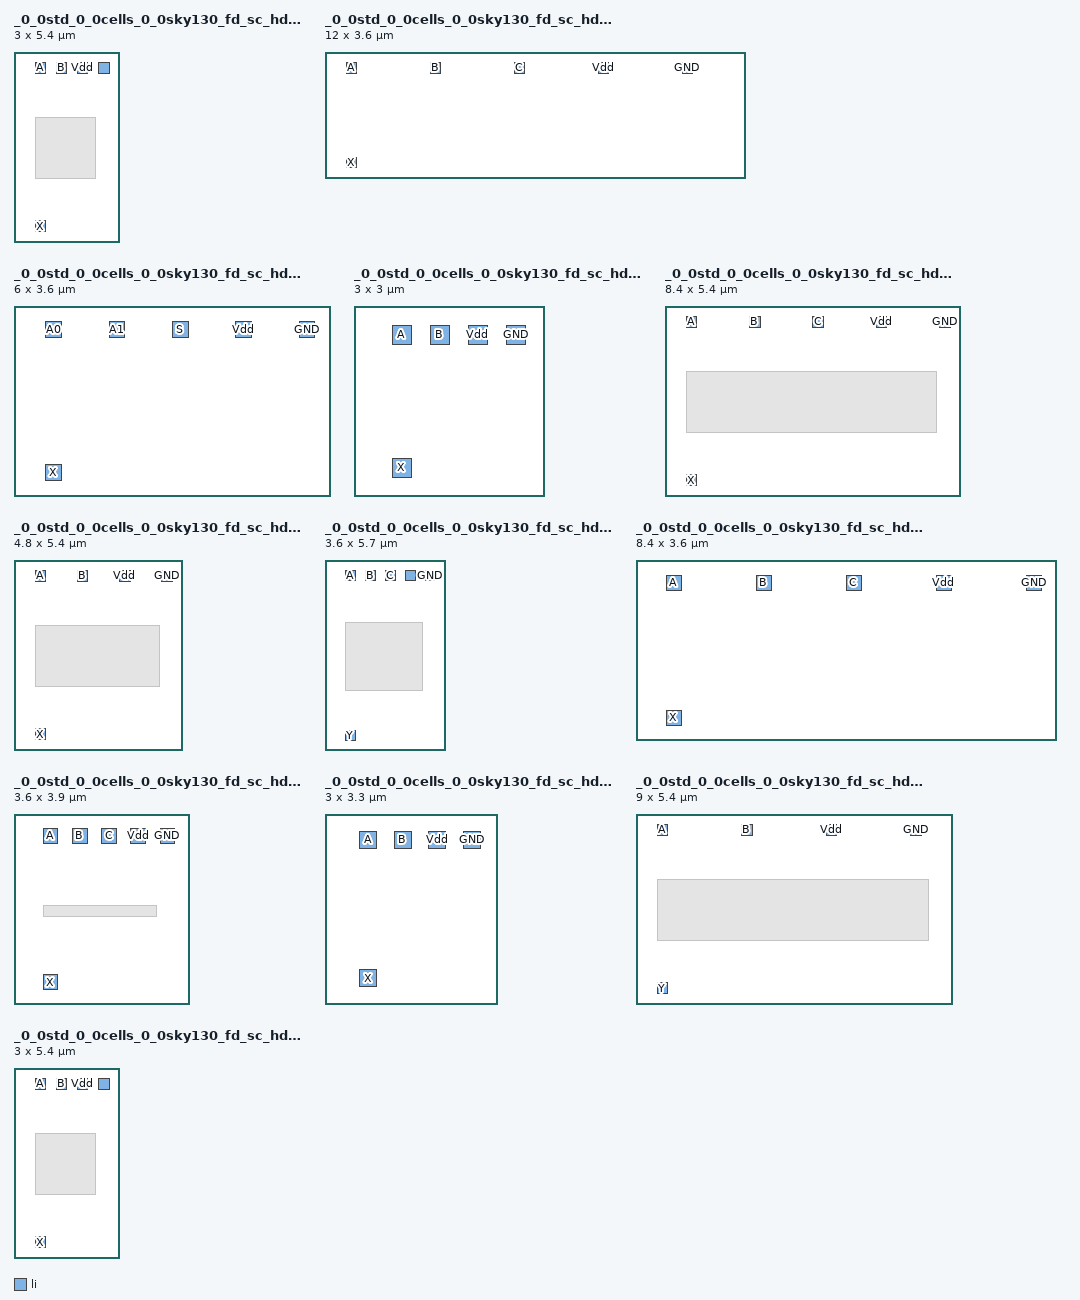
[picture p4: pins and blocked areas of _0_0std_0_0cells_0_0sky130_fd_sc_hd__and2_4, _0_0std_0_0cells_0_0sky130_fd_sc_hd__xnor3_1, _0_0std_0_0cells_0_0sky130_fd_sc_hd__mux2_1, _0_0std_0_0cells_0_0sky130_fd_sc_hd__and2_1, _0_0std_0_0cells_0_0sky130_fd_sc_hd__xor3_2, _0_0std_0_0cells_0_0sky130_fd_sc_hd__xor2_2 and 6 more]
MACRO _0_0std_0_0cells_0_0sky130_fd_sc_hd__and2_4
    CLASS CORE ;
    FOREIGN _0_0std_0_0cells_0_0sky130_fd_sc_hd__and2_4 0.000000 0.000000 ;
    ORIGIN 0.000000 0.000000 ;
    SIZE 3.000000 BY 5.400000 ;
    SYMMETRY X Y ;
    SITE CoreSite ;
    PIN A
        DIRECTION INPUT ;
        USE SIGNAL ;
        PORT
        LAYER li ;
        RECT 0.600000 4.800000 0.900000 5.100000 ;
        END
    END A
    PIN B
        DIRECTION INPUT ;
        USE SIGNAL ;
        PORT
        LAYER li ;
        RECT 1.200000 4.800000 1.500000 5.100000 ;
        END
    END B
    PIN X
        DIRECTION OUTPUT ;
        USE SIGNAL ;
        PORT
        LAYER li ;
        RECT 0.600000 0.300000 0.900000 0.600000 ;
        END
        ANTENNADIFFAREA 1.406250 ;
    END X
    PIN Vdd
        DIRECTION INPUT ;
        USE POWER ;
        PORT
        LAYER li ;
        RECT 1.800000 4.800000 2.100000 5.100000 ;
        END
        ANTENNADIFFAREA 0.360000 ;
    END Vdd
    PIN GND
        DIRECTION INPUT ;
        USE GROUND ;
        PORT
        LAYER li ;
        RECT 2.400000 4.800000 2.700000 5.100000 ;
        END
        ANTENNADIFFAREA 0.168750 ;
    END GND
    OBS
      LAYER li ;
         RECT 0.600000 1.800000 2.325000 3.525000 ;
    END
END _0_0std_0_0cells_0_0sky130_fd_sc_hd__and2_4

MACRO _0_0std_0_0cells_0_0sky130_fd_sc_hd__xnor3_1
    CLASS CORE ;
    FOREIGN _0_0std_0_0cells_0_0sky130_fd_sc_hd__xnor3_1 0.000000 0.000000 ;
    ORIGIN 0.000000 0.000000 ;
    SIZE 12.000000 BY 3.600000 ;
    SYMMETRY X Y ;
    SITE CoreSite ;
    PIN A
        DIRECTION INPUT ;
        USE SIGNAL ;
        PORT
        LAYER li ;
        RECT 0.600000 3.000000 0.900000 3.300000 ;
        END
    END A
    PIN B
        DIRECTION INPUT ;
        USE SIGNAL ;
        PORT
        LAYER li ;
        RECT 3.000000 3.000000 3.300000 3.300000 ;
        END
    END B
    PIN C
        DIRECTION INPUT ;
        USE SIGNAL ;
        PORT
        LAYER li ;
        RECT 5.400000 3.000000 5.700000 3.300000 ;
        END
    END C
    PIN X
        DIRECTION OUTPUT ;
        USE SIGNAL ;
        PORT
        LAYER li ;
        RECT 0.600000 0.300000 0.900000 0.600000 ;
        END
        ANTENNADIFFAREA 0.928125 ;
    END X
    PIN Vdd
        DIRECTION INPUT ;
        USE POWER ;
        PORT
        LAYER li ;
        RECT 7.800000 3.000000 8.100000 3.300000 ;
        END
        ANTENNADIFFAREA 0.607500 ;
    END Vdd
    PIN GND
        DIRECTION INPUT ;
        USE GROUND ;
        PORT
        LAYER li ;
        RECT 10.200000 3.000000 10.500000 3.300000 ;
        END
        ANTENNADIFFAREA 0.776250 ;
    END GND
END _0_0std_0_0cells_0_0sky130_fd_sc_hd__xnor3_1

MACRO _0_0std_0_0cells_0_0sky130_fd_sc_hd__mux2_1
    CLASS CORE ;
    FOREIGN _0_0std_0_0cells_0_0sky130_fd_sc_hd__mux2_1 0.000000 0.000000 ;
    ORIGIN 0.000000 0.000000 ;
    SIZE 6.000000 BY 3.600000 ;
    SYMMETRY X Y ;
    SITE CoreSite ;
    PIN A0
        DIRECTION INPUT ;
        USE SIGNAL ;
        PORT
        LAYER li ;
        RECT 0.600000 3.000000 0.900000 3.300000 ;
        END
    END A0
    PIN A1
        DIRECTION INPUT ;
        USE SIGNAL ;
        PORT
        LAYER li ;
        RECT 1.800000 3.000000 2.100000 3.300000 ;
        END
    END A1
    PIN S
        DIRECTION INPUT ;
        USE SIGNAL ;
        PORT
        LAYER li ;
        RECT 3.000000 3.000000 3.300000 3.300000 ;
        END
    END S
    PIN X
        DIRECTION OUTPUT ;
        USE SIGNAL ;
        PORT
        LAYER li ;
        RECT 0.600000 0.300000 0.900000 0.600000 ;
        END
        ANTENNADIFFAREA 0.393750 ;
    END X
    PIN Vdd
        DIRECTION INPUT ;
        USE POWER ;
        PORT
        LAYER li ;
        RECT 4.200000 3.000000 4.500000 3.300000 ;
        END
        ANTENNADIFFAREA 1.068750 ;
    END Vdd
    PIN GND
        DIRECTION INPUT ;
        USE GROUND ;
        PORT
        LAYER li ;
        RECT 5.400000 3.000000 5.700000 3.300000 ;
        END
        ANTENNADIFFAREA 0.450000 ;
    END GND
END _0_0std_0_0cells_0_0sky130_fd_sc_hd__mux2_1

MACRO _0_0std_0_0cells_0_0sky130_fd_sc_hd__and2_1
    CLASS CORE ;
    FOREIGN _0_0std_0_0cells_0_0sky130_fd_sc_hd__and2_1 0.000000 0.000000 ;
    ORIGIN 0.000000 0.000000 ;
    SIZE 3.000000 BY 3.000000 ;
    SYMMETRY X Y ;
    SITE CoreSite ;
    PIN A
        DIRECTION INPUT ;
        USE SIGNAL ;
        PORT
        LAYER li ;
        RECT 0.600000 2.400000 0.900000 2.700000 ;
        END
    END A
    PIN B
        DIRECTION INPUT ;
        USE SIGNAL ;
        PORT
        LAYER li ;
        RECT 1.200000 2.400000 1.500000 2.700000 ;
        END
    END B
    PIN X
        DIRECTION OUTPUT ;
        USE SIGNAL ;
        PORT
        LAYER li ;
        RECT 0.600000 0.300000 0.900000 0.600000 ;
        END
        ANTENNADIFFAREA 0.393750 ;
    END X
    PIN Vdd
        DIRECTION INPUT ;
        USE POWER ;
        PORT
        LAYER li ;
        RECT 1.800000 2.400000 2.100000 2.700000 ;
        END
        ANTENNADIFFAREA 0.450000 ;
    END Vdd
    PIN GND
        DIRECTION INPUT ;
        USE GROUND ;
        PORT
        LAYER li ;
        RECT 2.400000 2.400000 2.700000 2.700000 ;
        END
        ANTENNADIFFAREA 0.225000 ;
    END GND
END _0_0std_0_0cells_0_0sky130_fd_sc_hd__and2_1

MACRO _0_0std_0_0cells_0_0sky130_fd_sc_hd__xor3_2
    CLASS CORE ;
    FOREIGN _0_0std_0_0cells_0_0sky130_fd_sc_hd__xor3_2 0.000000 0.000000 ;
    ORIGIN 0.000000 0.000000 ;
    SIZE 8.400000 BY 5.400000 ;
    SYMMETRY X Y ;
    SITE CoreSite ;
    PIN A
        DIRECTION INPUT ;
        USE SIGNAL ;
        PORT
        LAYER li ;
        RECT 0.600000 4.800000 0.900000 5.100000 ;
        END
    END A
    PIN B
        DIRECTION INPUT ;
        USE SIGNAL ;
        PORT
        LAYER li ;
        RECT 2.400000 4.800000 2.700000 5.100000 ;
        END
    END B
    PIN C
        DIRECTION INPUT ;
        USE SIGNAL ;
        PORT
        LAYER li ;
        RECT 4.200000 4.800000 4.500000 5.100000 ;
        END
    END C
    PIN X
        DIRECTION OUTPUT ;
        USE SIGNAL ;
        PORT
        LAYER li ;
        RECT 0.600000 0.300000 0.900000 0.600000 ;
        END
        ANTENNADIFFAREA 1.293750 ;
    END X
    PIN Vdd
        DIRECTION INPUT ;
        USE POWER ;
        PORT
        LAYER li ;
        RECT 6.000000 4.800000 6.300000 5.100000 ;
        END
        ANTENNADIFFAREA 1.096875 ;
    END Vdd
    PIN GND
        DIRECTION INPUT ;
        USE GROUND ;
        PORT
        LAYER li ;
        RECT 7.800000 4.800000 8.100000 5.100000 ;
        END
        ANTENNADIFFAREA 1.575000 ;
    END GND
    OBS
      LAYER li ;
         RECT 0.600000 1.800000 7.725000 3.525000 ;
    END
END _0_0std_0_0cells_0_0sky130_fd_sc_hd__xor3_2

MACRO _0_0std_0_0cells_0_0sky130_fd_sc_hd__xor2_2
    CLASS CORE ;
    FOREIGN _0_0std_0_0cells_0_0sky130_fd_sc_hd__xor2_2 0.000000 0.000000 ;
    ORIGIN 0.000000 0.000000 ;
    SIZE 4.800000 BY 5.400000 ;
    SYMMETRY X Y ;
    SITE CoreSite ;
    PIN A
        DIRECTION INPUT ;
        USE SIGNAL ;
        PORT
        LAYER li ;
        RECT 0.600000 4.800000 0.900000 5.100000 ;
        END
    END A
    PIN B
        DIRECTION INPUT ;
        USE SIGNAL ;
        PORT
        LAYER li ;
        RECT 1.800000 4.800000 2.100000 5.100000 ;
        END
    END B
    PIN X
        DIRECTION OUTPUT ;
        USE SIGNAL ;
        PORT
        LAYER li ;
        RECT 0.600000 0.300000 0.900000 0.600000 ;
        END
        ANTENNADIFFAREA 1.293750 ;
    END X
    PIN Vdd
        DIRECTION INPUT ;
        USE POWER ;
        PORT
        LAYER li ;
        RECT 3.000000 4.800000 3.300000 5.100000 ;
        END
        ANTENNADIFFAREA 0.675000 ;
    END Vdd
    PIN GND
        DIRECTION INPUT ;
        USE GROUND ;
        PORT
        LAYER li ;
        RECT 4.200000 4.800000 4.500000 5.100000 ;
        END
        ANTENNADIFFAREA 0.956250 ;
    END GND
    OBS
      LAYER li ;
         RECT 0.600000 1.800000 4.125000 3.525000 ;
    END
END _0_0std_0_0cells_0_0sky130_fd_sc_hd__xor2_2

MACRO _0_0std_0_0cells_0_0sky130_fd_sc_hd__nor3_2
    CLASS CORE ;
    FOREIGN _0_0std_0_0cells_0_0sky130_fd_sc_hd__nor3_2 0.000000 0.000000 ;
    ORIGIN 0.000000 0.000000 ;
    SIZE 3.600000 BY 5.700000 ;
    SYMMETRY X Y ;
    SITE CoreSite ;
    PIN A
        DIRECTION INPUT ;
        USE SIGNAL ;
        PORT
        LAYER li ;
        RECT 0.600000 5.100000 0.900000 5.400000 ;
        END
    END A
    PIN B
        DIRECTION INPUT ;
        USE SIGNAL ;
        PORT
        LAYER li ;
        RECT 1.200000 5.100000 1.500000 5.400000 ;
        END
    END B
    PIN C
        DIRECTION INPUT ;
        USE SIGNAL ;
        PORT
        LAYER li ;
        RECT 1.800000 5.100000 2.100000 5.400000 ;
        END
    END C
    PIN Y
        DIRECTION OUTPUT ;
        USE SIGNAL ;
        PORT
        LAYER li ;
        RECT 0.600000 0.300000 0.900000 0.600000 ;
        END
        ANTENNADIFFAREA 1.828125 ;
    END Y
    PIN Vdd
        DIRECTION INPUT ;
        USE POWER ;
        PORT
        LAYER li ;
        RECT 2.400000 5.100000 2.700000 5.400000 ;
        END
        ANTENNADIFFAREA 1.265625 ;
    END Vdd
    PIN GND
        DIRECTION INPUT ;
        USE GROUND ;
        PORT
        LAYER li ;
        RECT 3.000000 5.100000 3.300000 5.400000 ;
        END
        ANTENNADIFFAREA 0.562500 ;
    END GND
    OBS
      LAYER li ;
         RECT 0.600000 1.800000 2.925000 3.825000 ;
    END
END _0_0std_0_0cells_0_0sky130_fd_sc_hd__nor3_2

MACRO _0_0std_0_0cells_0_0sky130_fd_sc_hd__xor3_1
    CLASS CORE ;
    FOREIGN _0_0std_0_0cells_0_0sky130_fd_sc_hd__xor3_1 0.000000 0.000000 ;
    ORIGIN 0.000000 0.000000 ;
    SIZE 8.400000 BY 3.600000 ;
    SYMMETRY X Y ;
    SITE CoreSite ;
    PIN A
        DIRECTION INPUT ;
        USE SIGNAL ;
        PORT
        LAYER li ;
        RECT 0.600000 3.000000 0.900000 3.300000 ;
        END
    END A
    PIN B
        DIRECTION INPUT ;
        USE SIGNAL ;
        PORT
        LAYER li ;
        RECT 2.400000 3.000000 2.700000 3.300000 ;
        END
    END B
    PIN C
        DIRECTION INPUT ;
        USE SIGNAL ;
        PORT
        LAYER li ;
        RECT 4.200000 3.000000 4.500000 3.300000 ;
        END
    END C
    PIN X
        DIRECTION OUTPUT ;
        USE SIGNAL ;
        PORT
        LAYER li ;
        RECT 0.600000 0.300000 0.900000 0.600000 ;
        END
        ANTENNADIFFAREA 0.646875 ;
    END X
    PIN Vdd
        DIRECTION INPUT ;
        USE POWER ;
        PORT
        LAYER li ;
        RECT 6.000000 3.000000 6.300000 3.300000 ;
        END
        ANTENNADIFFAREA 0.843750 ;
    END Vdd
    PIN GND
        DIRECTION INPUT ;
        USE GROUND ;
        PORT
        LAYER li ;
        RECT 7.800000 3.000000 8.100000 3.300000 ;
        END
        ANTENNADIFFAREA 1.237500 ;
    END GND
END _0_0std_0_0cells_0_0sky130_fd_sc_hd__xor3_1

MACRO _0_0std_0_0cells_0_0sky130_fd_sc_hd__or3_1
    CLASS CORE ;
    FOREIGN _0_0std_0_0cells_0_0sky130_fd_sc_hd__or3_1 0.000000 0.000000 ;
    ORIGIN 0.000000 0.000000 ;
    SIZE 3.600000 BY 3.900000 ;
    SYMMETRY X Y ;
    SITE CoreSite ;
    PIN A
        DIRECTION INPUT ;
        USE SIGNAL ;
        PORT
        LAYER li ;
        RECT 0.600000 3.300000 0.900000 3.600000 ;
        END
    END A
    PIN B
        DIRECTION INPUT ;
        USE SIGNAL ;
        PORT
        LAYER li ;
        RECT 1.200000 3.300000 1.500000 3.600000 ;
        END
    END B
    PIN C
        DIRECTION INPUT ;
        USE SIGNAL ;
        PORT
        LAYER li ;
        RECT 1.800000 3.300000 2.100000 3.600000 ;
        END
    END C
    PIN X
        DIRECTION OUTPUT ;
        USE SIGNAL ;
        PORT
        LAYER li ;
        RECT 0.600000 0.300000 0.900000 0.600000 ;
        END
        ANTENNADIFFAREA 0.393750 ;
    END X
    PIN Vdd
        DIRECTION INPUT ;
        USE POWER ;
        PORT
        LAYER li ;
        RECT 2.400000 3.300000 2.700000 3.600000 ;
        END
        ANTENNADIFFAREA 0.517500 ;
    END Vdd
    PIN GND
        DIRECTION INPUT ;
        USE GROUND ;
        PORT
        LAYER li ;
        RECT 3.000000 3.300000 3.300000 3.600000 ;
        END
        ANTENNADIFFAREA 0.337500 ;
    END GND
    OBS
      LAYER li ;
         RECT 0.600000 1.800000 2.925000 2.025000 ;
    END
END _0_0std_0_0cells_0_0sky130_fd_sc_hd__or3_1

MACRO _0_0std_0_0cells_0_0sky130_fd_sc_hd__or2_1
    CLASS CORE ;
    FOREIGN _0_0std_0_0cells_0_0sky130_fd_sc_hd__or2_1 0.000000 0.000000 ;
    ORIGIN 0.000000 0.000000 ;
    SIZE 3.000000 BY 3.300000 ;
    SYMMETRY X Y ;
    SITE CoreSite ;
    PIN A
        DIRECTION INPUT ;
        USE SIGNAL ;
        PORT
        LAYER li ;
        RECT 0.600000 2.700000 0.900000 3.000000 ;
        END
    END A
    PIN B
        DIRECTION INPUT ;
        USE SIGNAL ;
        PORT
        LAYER li ;
        RECT 1.200000 2.700000 1.500000 3.000000 ;
        END
    END B
    PIN X
        DIRECTION OUTPUT ;
        USE SIGNAL ;
        PORT
        LAYER li ;
        RECT 0.600000 0.300000 0.900000 0.600000 ;
        END
        ANTENNADIFFAREA 0.393750 ;
    END X
    PIN Vdd
        DIRECTION INPUT ;
        USE POWER ;
        PORT
        LAYER li ;
        RECT 1.800000 2.700000 2.100000 3.000000 ;
        END
        ANTENNADIFFAREA 0.337500 ;
    END Vdd
    PIN GND
        DIRECTION INPUT ;
        USE GROUND ;
        PORT
        LAYER li ;
        RECT 2.400000 2.700000 2.700000 3.000000 ;
        END
        ANTENNADIFFAREA 0.337500 ;
    END GND
END _0_0std_0_0cells_0_0sky130_fd_sc_hd__or2_1

MACRO _0_0std_0_0cells_0_0sky130_fd_sc_hd__xnor2_2
    CLASS CORE ;
    FOREIGN _0_0std_0_0cells_0_0sky130_fd_sc_hd__xnor2_2 0.000000 0.000000 ;
    ORIGIN 0.000000 0.000000 ;
    SIZE 9.000000 BY 5.400000 ;
    SYMMETRY X Y ;
    SITE CoreSite ;
    PIN A
        DIRECTION INPUT ;
        USE SIGNAL ;
        PORT
        LAYER li ;
        RECT 0.600000 4.800000 0.900000 5.100000 ;
        END
    END A
    PIN B
        DIRECTION INPUT ;
        USE SIGNAL ;
        PORT
        LAYER li ;
        RECT 3.000000 4.800000 3.300000 5.100000 ;
        END
    END B
    PIN Y
        DIRECTION OUTPUT ;
        USE SIGNAL ;
        PORT
        LAYER li ;
        RECT 0.600000 0.300000 0.900000 0.600000 ;
        END
        ANTENNADIFFAREA 0.815625 ;
    END Y
    PIN Vdd
        DIRECTION INPUT ;
        USE POWER ;
        PORT
        LAYER li ;
        RECT 5.400000 4.800000 5.700000 5.100000 ;
        END
        ANTENNADIFFAREA 1.321875 ;
    END Vdd
    PIN GND
        DIRECTION INPUT ;
        USE GROUND ;
        PORT
        LAYER li ;
        RECT 7.800000 4.800000 8.100000 5.100000 ;
        END
        ANTENNADIFFAREA 1.237500 ;
    END GND
    OBS
      LAYER li ;
         RECT 0.600000 1.800000 8.325000 3.525000 ;
    END
END _0_0std_0_0cells_0_0sky130_fd_sc_hd__xnor2_2

MACRO _0_0std_0_0cells_0_0sky130_fd_sc_hd__or2_4
    CLASS CORE ;
    FOREIGN _0_0std_0_0cells_0_0sky130_fd_sc_hd__or2_4 0.000000 0.000000 ;
    ORIGIN 0.000000 0.000000 ;
    SIZE 3.000000 BY 5.400000 ;
    SYMMETRY X Y ;
    SITE CoreSite ;
    PIN A
        DIRECTION INPUT ;
        USE SIGNAL ;
        PORT
        LAYER li ;
        RECT 0.600000 4.800000 0.900000 5.100000 ;
        END
    END A
    PIN B
        DIRECTION INPUT ;
        USE SIGNAL ;
        PORT
        LAYER li ;
        RECT 1.200000 4.800000 1.500000 5.100000 ;
        END
    END B
    PIN X
        DIRECTION OUTPUT ;
        USE SIGNAL ;
        PORT
        LAYER li ;
        RECT 0.600000 0.300000 0.900000 0.600000 ;
        END
        ANTENNADIFFAREA 1.406250 ;
    END X
    PIN Vdd
        DIRECTION INPUT ;
        USE POWER ;
        PORT
        LAYER li ;
        RECT 1.800000 4.800000 2.100000 5.100000 ;
        END
        ANTENNADIFFAREA 0.253125 ;
    END Vdd
    PIN GND
        DIRECTION INPUT ;
        USE GROUND ;
        PORT
        LAYER li ;
        RECT 2.400000 4.800000 2.700000 5.100000 ;
        END
        ANTENNADIFFAREA 0.270000 ;
    END GND
    OBS
      LAYER li ;
         RECT 0.600000 1.800000 2.325000 3.525000 ;
    END
END _0_0std_0_0cells_0_0sky130_fd_sc_hd__or2_4

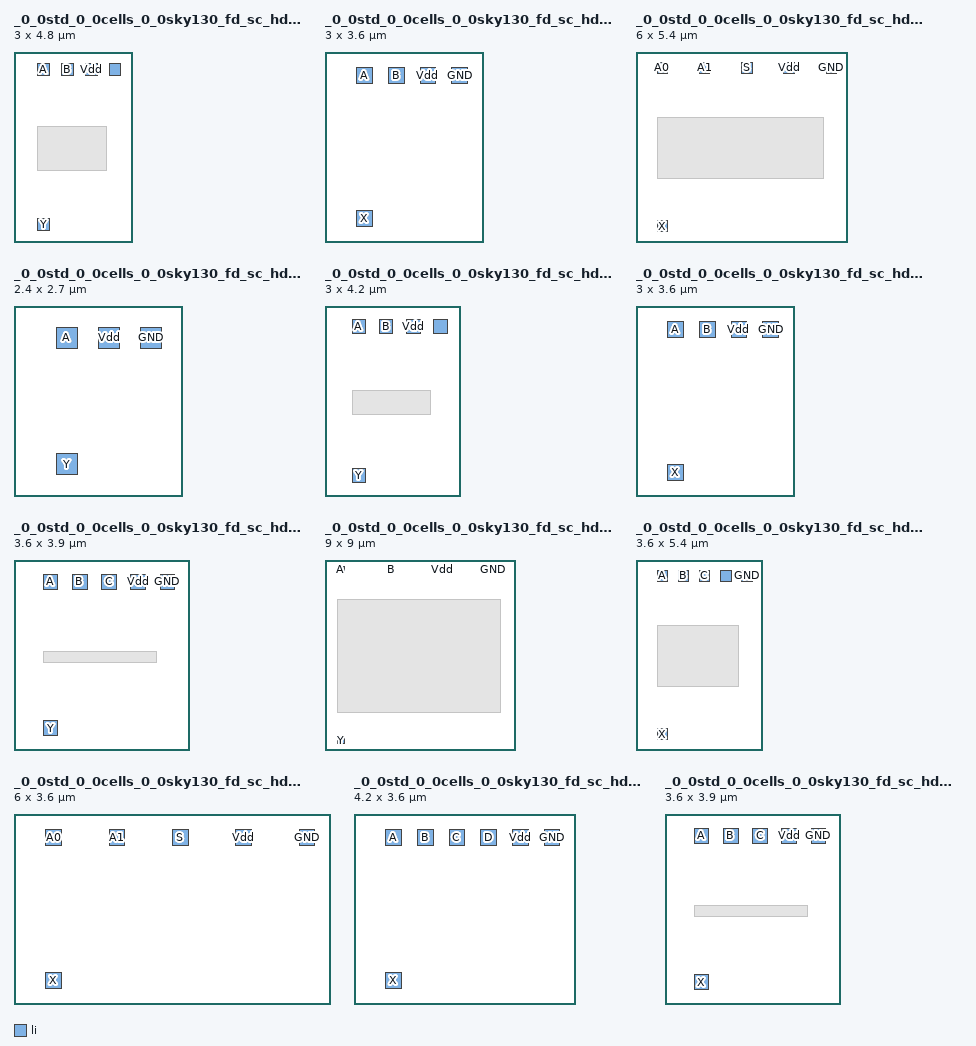
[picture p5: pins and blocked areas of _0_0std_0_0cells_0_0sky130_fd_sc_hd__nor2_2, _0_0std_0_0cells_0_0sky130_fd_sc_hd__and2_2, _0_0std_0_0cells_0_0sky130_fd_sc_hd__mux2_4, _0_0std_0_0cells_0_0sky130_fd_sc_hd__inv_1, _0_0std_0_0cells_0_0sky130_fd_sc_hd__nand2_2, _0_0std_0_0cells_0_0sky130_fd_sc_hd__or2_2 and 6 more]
MACRO _0_0std_0_0cells_0_0sky130_fd_sc_hd__nor2_2
    CLASS CORE ;
    FOREIGN _0_0std_0_0cells_0_0sky130_fd_sc_hd__nor2_2 0.000000 0.000000 ;
    ORIGIN 0.000000 0.000000 ;
    SIZE 3.000000 BY 4.800000 ;
    SYMMETRY X Y ;
    SITE CoreSite ;
    PIN A
        DIRECTION INPUT ;
        USE SIGNAL ;
        PORT
        LAYER li ;
        RECT 0.600000 4.200000 0.900000 4.500000 ;
        END
    END A
    PIN B
        DIRECTION INPUT ;
        USE SIGNAL ;
        PORT
        LAYER li ;
        RECT 1.200000 4.200000 1.500000 4.500000 ;
        END
    END B
    PIN Y
        DIRECTION OUTPUT ;
        USE SIGNAL ;
        PORT
        LAYER li ;
        RECT 0.600000 0.300000 0.900000 0.600000 ;
        END
        ANTENNADIFFAREA 1.125000 ;
    END Y
    PIN Vdd
        DIRECTION INPUT ;
        USE POWER ;
        PORT
        LAYER li ;
        RECT 1.800000 4.200000 2.100000 4.500000 ;
        END
        ANTENNADIFFAREA 0.843750 ;
    END Vdd
    PIN GND
        DIRECTION INPUT ;
        USE GROUND ;
        PORT
        LAYER li ;
        RECT 2.400000 4.200000 2.700000 4.500000 ;
        END
        ANTENNADIFFAREA 0.562500 ;
    END GND
    OBS
      LAYER li ;
         RECT 0.600000 1.800000 2.325000 2.925000 ;
    END
END _0_0std_0_0cells_0_0sky130_fd_sc_hd__nor2_2

MACRO _0_0std_0_0cells_0_0sky130_fd_sc_hd__and2_2
    CLASS CORE ;
    FOREIGN _0_0std_0_0cells_0_0sky130_fd_sc_hd__and2_2 0.000000 0.000000 ;
    ORIGIN 0.000000 0.000000 ;
    SIZE 3.000000 BY 3.600000 ;
    SYMMETRY X Y ;
    SITE CoreSite ;
    PIN A
        DIRECTION INPUT ;
        USE SIGNAL ;
        PORT
        LAYER li ;
        RECT 0.600000 3.000000 0.900000 3.300000 ;
        END
    END A
    PIN B
        DIRECTION INPUT ;
        USE SIGNAL ;
        PORT
        LAYER li ;
        RECT 1.200000 3.000000 1.500000 3.300000 ;
        END
    END B
    PIN X
        DIRECTION OUTPUT ;
        USE SIGNAL ;
        PORT
        LAYER li ;
        RECT 0.600000 0.300000 0.900000 0.600000 ;
        END
        ANTENNADIFFAREA 0.703125 ;
    END X
    PIN Vdd
        DIRECTION INPUT ;
        USE POWER ;
        PORT
        LAYER li ;
        RECT 1.800000 3.000000 2.100000 3.300000 ;
        END
        ANTENNADIFFAREA 0.360000 ;
    END Vdd
    PIN GND
        DIRECTION INPUT ;
        USE GROUND ;
        PORT
        LAYER li ;
        RECT 2.400000 3.000000 2.700000 3.300000 ;
        END
        ANTENNADIFFAREA 0.393750 ;
    END GND
END _0_0std_0_0cells_0_0sky130_fd_sc_hd__and2_2

MACRO _0_0std_0_0cells_0_0sky130_fd_sc_hd__mux2_4
    CLASS CORE ;
    FOREIGN _0_0std_0_0cells_0_0sky130_fd_sc_hd__mux2_4 0.000000 0.000000 ;
    ORIGIN 0.000000 0.000000 ;
    SIZE 6.000000 BY 5.400000 ;
    SYMMETRY X Y ;
    SITE CoreSite ;
    PIN A0
        DIRECTION INPUT ;
        USE SIGNAL ;
        PORT
        LAYER li ;
        RECT 0.600000 4.800000 0.900000 5.100000 ;
        END
    END A0
    PIN A1
        DIRECTION INPUT ;
        USE SIGNAL ;
        PORT
        LAYER li ;
        RECT 1.800000 4.800000 2.100000 5.100000 ;
        END
    END A1
    PIN S
        DIRECTION INPUT ;
        USE SIGNAL ;
        PORT
        LAYER li ;
        RECT 3.000000 4.800000 3.300000 5.100000 ;
        END
    END S
    PIN X
        DIRECTION OUTPUT ;
        USE SIGNAL ;
        PORT
        LAYER li ;
        RECT 0.600000 0.300000 0.900000 0.600000 ;
        END
        ANTENNADIFFAREA 1.406250 ;
    END X
    PIN Vdd
        DIRECTION INPUT ;
        USE POWER ;
        PORT
        LAYER li ;
        RECT 4.200000 4.800000 4.500000 5.100000 ;
        END
        ANTENNADIFFAREA 0.978750 ;
    END Vdd
    PIN GND
        DIRECTION INPUT ;
        USE GROUND ;
        PORT
        LAYER li ;
        RECT 5.400000 4.800000 5.700000 5.100000 ;
        END
        ANTENNADIFFAREA 0.382500 ;
    END GND
    OBS
      LAYER li ;
         RECT 0.600000 1.800000 5.325000 3.525000 ;
    END
END _0_0std_0_0cells_0_0sky130_fd_sc_hd__mux2_4

MACRO _0_0std_0_0cells_0_0sky130_fd_sc_hd__inv_1
    CLASS CORE ;
    FOREIGN _0_0std_0_0cells_0_0sky130_fd_sc_hd__inv_1 0.000000 0.000000 ;
    ORIGIN 0.000000 0.000000 ;
    SIZE 2.400000 BY 2.700000 ;
    SYMMETRY X Y ;
    SITE CoreSite ;
    PIN A
        DIRECTION INPUT ;
        USE SIGNAL ;
        PORT
        LAYER li ;
        RECT 0.600000 2.100000 0.900000 2.400000 ;
        END
    END A
    PIN Y
        DIRECTION OUTPUT ;
        USE SIGNAL ;
        PORT
        LAYER li ;
        RECT 0.600000 0.300000 0.900000 0.600000 ;
        END
        ANTENNADIFFAREA 0.393750 ;
    END Y
    PIN Vdd
        DIRECTION INPUT ;
        USE POWER ;
        PORT
        LAYER li ;
        RECT 1.200000 2.100000 1.500000 2.400000 ;
        END
        ANTENNADIFFAREA 0.225000 ;
    END Vdd
    PIN GND
        DIRECTION INPUT ;
        USE GROUND ;
        PORT
        LAYER li ;
        RECT 1.800000 2.100000 2.100000 2.400000 ;
        END
        ANTENNADIFFAREA 0.168750 ;
    END GND
END _0_0std_0_0cells_0_0sky130_fd_sc_hd__inv_1

MACRO _0_0std_0_0cells_0_0sky130_fd_sc_hd__nand2_2
    CLASS CORE ;
    FOREIGN _0_0std_0_0cells_0_0sky130_fd_sc_hd__nand2_2 0.000000 0.000000 ;
    ORIGIN 0.000000 0.000000 ;
    SIZE 3.000000 BY 4.200000 ;
    SYMMETRY X Y ;
    SITE CoreSite ;
    PIN A
        DIRECTION INPUT ;
        USE SIGNAL ;
        PORT
        LAYER li ;
        RECT 0.600000 3.600000 0.900000 3.900000 ;
        END
    END A
    PIN B
        DIRECTION INPUT ;
        USE SIGNAL ;
        PORT
        LAYER li ;
        RECT 1.200000 3.600000 1.500000 3.900000 ;
        END
    END B
    PIN Y
        DIRECTION OUTPUT ;
        USE SIGNAL ;
        PORT
        LAYER li ;
        RECT 0.600000 0.300000 0.900000 0.600000 ;
        END
        ANTENNADIFFAREA 0.984375 ;
    END Y
    PIN Vdd
        DIRECTION INPUT ;
        USE POWER ;
        PORT
        LAYER li ;
        RECT 1.800000 3.600000 2.100000 3.900000 ;
        END
        ANTENNADIFFAREA 0.843750 ;
    END Vdd
    PIN GND
        DIRECTION INPUT ;
        USE GROUND ;
        PORT
        LAYER li ;
        RECT 2.400000 3.600000 2.700000 3.900000 ;
        END
        ANTENNADIFFAREA 0.562500 ;
    END GND
    OBS
      LAYER li ;
         RECT 0.600000 1.800000 2.325000 2.325000 ;
    END
END _0_0std_0_0cells_0_0sky130_fd_sc_hd__nand2_2

MACRO _0_0std_0_0cells_0_0sky130_fd_sc_hd__or2_2
    CLASS CORE ;
    FOREIGN _0_0std_0_0cells_0_0sky130_fd_sc_hd__or2_2 0.000000 0.000000 ;
    ORIGIN 0.000000 0.000000 ;
    SIZE 3.000000 BY 3.600000 ;
    SYMMETRY X Y ;
    SITE CoreSite ;
    PIN A
        DIRECTION INPUT ;
        USE SIGNAL ;
        PORT
        LAYER li ;
        RECT 0.600000 3.000000 0.900000 3.300000 ;
        END
    END A
    PIN B
        DIRECTION INPUT ;
        USE SIGNAL ;
        PORT
        LAYER li ;
        RECT 1.200000 3.000000 1.500000 3.300000 ;
        END
    END B
    PIN X
        DIRECTION OUTPUT ;
        USE SIGNAL ;
        PORT
        LAYER li ;
        RECT 0.600000 0.300000 0.900000 0.600000 ;
        END
        ANTENNADIFFAREA 0.703125 ;
    END X
    PIN Vdd
        DIRECTION INPUT ;
        USE POWER ;
        PORT
        LAYER li ;
        RECT 1.800000 3.000000 2.100000 3.300000 ;
        END
        ANTENNADIFFAREA 0.590625 ;
    END Vdd
    PIN GND
        DIRECTION INPUT ;
        USE GROUND ;
        PORT
        LAYER li ;
        RECT 2.400000 3.000000 2.700000 3.300000 ;
        END
        ANTENNADIFFAREA 0.270000 ;
    END GND
END _0_0std_0_0cells_0_0sky130_fd_sc_hd__or2_2

MACRO _0_0std_0_0cells_0_0sky130_fd_sc_hd__nor3_1
    CLASS CORE ;
    FOREIGN _0_0std_0_0cells_0_0sky130_fd_sc_hd__nor3_1 0.000000 0.000000 ;
    ORIGIN 0.000000 0.000000 ;
    SIZE 3.600000 BY 3.900000 ;
    SYMMETRY X Y ;
    SITE CoreSite ;
    PIN A
        DIRECTION INPUT ;
        USE SIGNAL ;
        PORT
        LAYER li ;
        RECT 0.600000 3.300000 0.900000 3.600000 ;
        END
    END A
    PIN B
        DIRECTION INPUT ;
        USE SIGNAL ;
        PORT
        LAYER li ;
        RECT 1.200000 3.300000 1.500000 3.600000 ;
        END
    END B
    PIN C
        DIRECTION INPUT ;
        USE SIGNAL ;
        PORT
        LAYER li ;
        RECT 1.800000 3.300000 2.100000 3.600000 ;
        END
    END C
    PIN Y
        DIRECTION OUTPUT ;
        USE SIGNAL ;
        PORT
        LAYER li ;
        RECT 0.600000 0.300000 0.900000 0.600000 ;
        END
        ANTENNADIFFAREA 0.984375 ;
    END Y
    PIN Vdd
        DIRECTION INPUT ;
        USE POWER ;
        PORT
        LAYER li ;
        RECT 2.400000 3.300000 2.700000 3.600000 ;
        END
        ANTENNADIFFAREA 0.646875 ;
    END Vdd
    PIN GND
        DIRECTION INPUT ;
        USE GROUND ;
        PORT
        LAYER li ;
        RECT 3.000000 3.300000 3.300000 3.600000 ;
        END
        ANTENNADIFFAREA 0.337500 ;
    END GND
    OBS
      LAYER li ;
         RECT 0.600000 1.800000 2.925000 2.025000 ;
    END
END _0_0std_0_0cells_0_0sky130_fd_sc_hd__nor3_1

MACRO _0_0std_0_0cells_0_0sky130_fd_sc_hd__xnor2_4
    CLASS CORE ;
    FOREIGN _0_0std_0_0cells_0_0sky130_fd_sc_hd__xnor2_4 0.000000 0.000000 ;
    ORIGIN 0.000000 0.000000 ;
    SIZE 9.000000 BY 9.000000 ;
    SYMMETRY X Y ;
    SITE CoreSite ;
    PIN A
        DIRECTION INPUT ;
        USE SIGNAL ;
        PORT
        LAYER li ;
        RECT 0.600000 8.400000 0.900000 8.700000 ;
        END
    END A
    PIN B
        DIRECTION INPUT ;
        USE SIGNAL ;
        PORT
        LAYER li ;
        RECT 3.000000 8.400000 3.300000 8.700000 ;
        END
    END B
    PIN Y
        DIRECTION OUTPUT ;
        USE SIGNAL ;
        PORT
        LAYER li ;
        RECT 0.600000 0.300000 0.900000 0.600000 ;
        END
        ANTENNADIFFAREA 1.631250 ;
    END Y
    PIN Vdd
        DIRECTION INPUT ;
        USE POWER ;
        PORT
        LAYER li ;
        RECT 5.400000 8.400000 5.700000 8.700000 ;
        END
        ANTENNADIFFAREA 2.418750 ;
    END Vdd
    PIN GND
        DIRECTION INPUT ;
        USE GROUND ;
        PORT
        LAYER li ;
        RECT 7.800000 8.400000 8.100000 8.700000 ;
        END
        ANTENNADIFFAREA 2.475000 ;
    END GND
    OBS
      LAYER li ;
         RECT 0.600000 1.800000 8.325000 7.125000 ;
    END
END _0_0std_0_0cells_0_0sky130_fd_sc_hd__xnor2_4

MACRO _0_0std_0_0cells_0_0sky130_fd_sc_hd__or3_4
    CLASS CORE ;
    FOREIGN _0_0std_0_0cells_0_0sky130_fd_sc_hd__or3_4 0.000000 0.000000 ;
    ORIGIN 0.000000 0.000000 ;
    SIZE 3.600000 BY 5.400000 ;
    SYMMETRY X Y ;
    SITE CoreSite ;
    PIN A
        DIRECTION INPUT ;
        USE SIGNAL ;
        PORT
        LAYER li ;
        RECT 0.600000 4.800000 0.900000 5.100000 ;
        END
    END A
    PIN B
        DIRECTION INPUT ;
        USE SIGNAL ;
        PORT
        LAYER li ;
        RECT 1.200000 4.800000 1.500000 5.100000 ;
        END
    END B
    PIN C
        DIRECTION INPUT ;
        USE SIGNAL ;
        PORT
        LAYER li ;
        RECT 1.800000 4.800000 2.100000 5.100000 ;
        END
    END C
    PIN X
        DIRECTION OUTPUT ;
        USE SIGNAL ;
        PORT
        LAYER li ;
        RECT 0.600000 0.300000 0.900000 0.600000 ;
        END
        ANTENNADIFFAREA 1.406250 ;
    END X
    PIN Vdd
        DIRECTION INPUT ;
        USE POWER ;
        PORT
        LAYER li ;
        RECT 2.400000 4.800000 2.700000 5.100000 ;
        END
        ANTENNADIFFAREA 0.388125 ;
    END Vdd
    PIN GND
        DIRECTION INPUT ;
        USE GROUND ;
        PORT
        LAYER li ;
        RECT 3.000000 4.800000 3.300000 5.100000 ;
        END
        ANTENNADIFFAREA 0.270000 ;
    END GND
    OBS
      LAYER li ;
         RECT 0.600000 1.800000 2.925000 3.525000 ;
    END
END _0_0std_0_0cells_0_0sky130_fd_sc_hd__or3_4

MACRO _0_0std_0_0cells_0_0sky130_fd_sc_hd__mux2_2
    CLASS CORE ;
    FOREIGN _0_0std_0_0cells_0_0sky130_fd_sc_hd__mux2_2 0.000000 0.000000 ;
    ORIGIN 0.000000 0.000000 ;
    SIZE 6.000000 BY 3.600000 ;
    SYMMETRY X Y ;
    SITE CoreSite ;
    PIN A0
        DIRECTION INPUT ;
        USE SIGNAL ;
        PORT
        LAYER li ;
        RECT 0.600000 3.000000 0.900000 3.300000 ;
        END
    END A0
    PIN A1
        DIRECTION INPUT ;
        USE SIGNAL ;
        PORT
        LAYER li ;
        RECT 1.800000 3.000000 2.100000 3.300000 ;
        END
    END A1
    PIN S
        DIRECTION INPUT ;
        USE SIGNAL ;
        PORT
        LAYER li ;
        RECT 3.000000 3.000000 3.300000 3.300000 ;
        END
    END S
    PIN X
        DIRECTION OUTPUT ;
        USE SIGNAL ;
        PORT
        LAYER li ;
        RECT 0.600000 0.300000 0.900000 0.600000 ;
        END
        ANTENNADIFFAREA 0.703125 ;
    END X
    PIN Vdd
        DIRECTION INPUT ;
        USE POWER ;
        PORT
        LAYER li ;
        RECT 4.200000 3.000000 4.500000 3.300000 ;
        END
        ANTENNADIFFAREA 0.978750 ;
    END Vdd
    PIN GND
        DIRECTION INPUT ;
        USE GROUND ;
        PORT
        LAYER li ;
        RECT 5.400000 3.000000 5.700000 3.300000 ;
        END
        ANTENNADIFFAREA 0.382500 ;
    END GND
END _0_0std_0_0cells_0_0sky130_fd_sc_hd__mux2_2

MACRO _0_0std_0_0cells_0_0sky130_fd_sc_hd__and4_1
    CLASS CORE ;
    FOREIGN _0_0std_0_0cells_0_0sky130_fd_sc_hd__and4_1 0.000000 0.000000 ;
    ORIGIN 0.000000 0.000000 ;
    SIZE 4.200000 BY 3.600000 ;
    SYMMETRY X Y ;
    SITE CoreSite ;
    PIN A
        DIRECTION INPUT ;
        USE SIGNAL ;
        PORT
        LAYER li ;
        RECT 0.600000 3.000000 0.900000 3.300000 ;
        END
    END A
    PIN B
        DIRECTION INPUT ;
        USE SIGNAL ;
        PORT
        LAYER li ;
        RECT 1.200000 3.000000 1.500000 3.300000 ;
        END
    END B
    PIN C
        DIRECTION INPUT ;
        USE SIGNAL ;
        PORT
        LAYER li ;
        RECT 1.800000 3.000000 2.100000 3.300000 ;
        END
    END C
    PIN D
        DIRECTION INPUT ;
        USE SIGNAL ;
        PORT
        LAYER li ;
        RECT 2.400000 3.000000 2.700000 3.300000 ;
        END
    END D
    PIN X
        DIRECTION OUTPUT ;
        USE SIGNAL ;
        PORT
        LAYER li ;
        RECT 0.600000 0.300000 0.900000 0.600000 ;
        END
        ANTENNADIFFAREA 0.393750 ;
    END X
    PIN Vdd
        DIRECTION INPUT ;
        USE POWER ;
        PORT
        LAYER li ;
        RECT 3.000000 3.000000 3.300000 3.300000 ;
        END
        ANTENNADIFFAREA 0.675000 ;
    END Vdd
    PIN GND
        DIRECTION INPUT ;
        USE GROUND ;
        PORT
        LAYER li ;
        RECT 3.600000 3.000000 3.900000 3.300000 ;
        END
        ANTENNADIFFAREA 0.450000 ;
    END GND
END _0_0std_0_0cells_0_0sky130_fd_sc_hd__and4_1

MACRO _0_0std_0_0cells_0_0sky130_fd_sc_hd__and3_2
    CLASS CORE ;
    FOREIGN _0_0std_0_0cells_0_0sky130_fd_sc_hd__and3_2 0.000000 0.000000 ;
    ORIGIN 0.000000 0.000000 ;
    SIZE 3.600000 BY 3.900000 ;
    SYMMETRY X Y ;
    SITE CoreSite ;
    PIN A
        DIRECTION INPUT ;
        USE SIGNAL ;
        PORT
        LAYER li ;
        RECT 0.600000 3.300000 0.900000 3.600000 ;
        END
    END A
    PIN B
        DIRECTION INPUT ;
        USE SIGNAL ;
        PORT
        LAYER li ;
        RECT 1.200000 3.300000 1.500000 3.600000 ;
        END
    END B
    PIN C
        DIRECTION INPUT ;
        USE SIGNAL ;
        PORT
        LAYER li ;
        RECT 1.800000 3.300000 2.100000 3.600000 ;
        END
    END C
    PIN X
        DIRECTION OUTPUT ;
        USE SIGNAL ;
        PORT
        LAYER li ;
        RECT 0.600000 0.300000 0.900000 0.600000 ;
        END
        ANTENNADIFFAREA 0.703125 ;
    END X
    PIN Vdd
        DIRECTION INPUT ;
        USE POWER ;
        PORT
        LAYER li ;
        RECT 2.400000 3.300000 2.700000 3.600000 ;
        END
        ANTENNADIFFAREA 0.360000 ;
    END Vdd
    PIN GND
        DIRECTION INPUT ;
        USE GROUND ;
        PORT
        LAYER li ;
        RECT 3.000000 3.300000 3.300000 3.600000 ;
        END
        ANTENNADIFFAREA 0.337500 ;
    END GND
    OBS
      LAYER li ;
         RECT 0.600000 1.800000 2.925000 2.025000 ;
    END
END _0_0std_0_0cells_0_0sky130_fd_sc_hd__and3_2

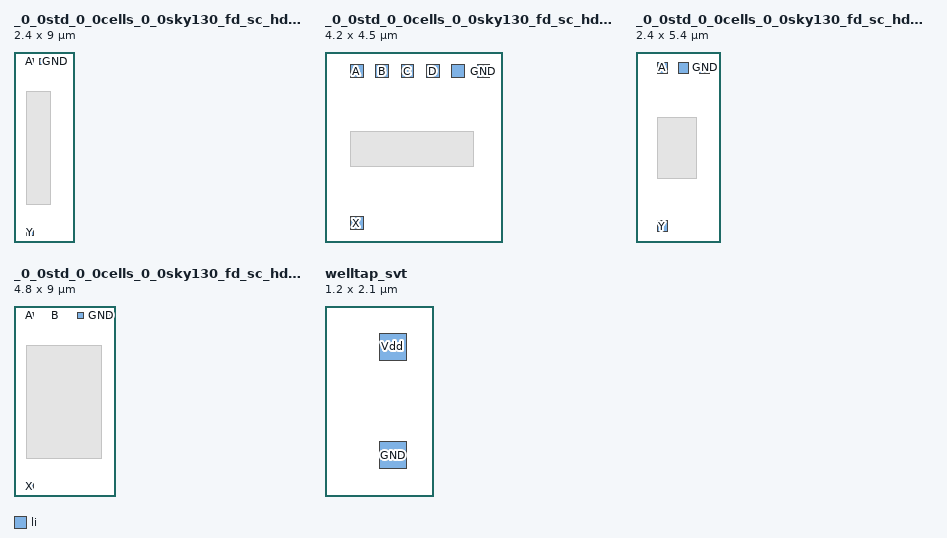
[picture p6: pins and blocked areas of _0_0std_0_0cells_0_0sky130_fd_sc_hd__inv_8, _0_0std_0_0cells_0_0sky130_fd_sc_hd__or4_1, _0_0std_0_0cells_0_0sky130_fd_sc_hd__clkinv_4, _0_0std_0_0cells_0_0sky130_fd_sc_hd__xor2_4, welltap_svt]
MACRO _0_0std_0_0cells_0_0sky130_fd_sc_hd__inv_8
    CLASS CORE ;
    FOREIGN _0_0std_0_0cells_0_0sky130_fd_sc_hd__inv_8 0.000000 0.000000 ;
    ORIGIN 0.000000 0.000000 ;
    SIZE 2.400000 BY 9.000000 ;
    SYMMETRY X Y ;
    SITE CoreSite ;
    PIN A
        DIRECTION INPUT ;
        USE SIGNAL ;
        PORT
        LAYER li ;
        RECT 0.600000 8.400000 0.900000 8.700000 ;
        END
    END A
    PIN Y
        DIRECTION OUTPUT ;
        USE SIGNAL ;
        PORT
        LAYER li ;
        RECT 0.600000 0.300000 0.900000 0.600000 ;
        END
        ANTENNADIFFAREA 2.812500 ;
    END Y
    PIN Vdd
        DIRECTION INPUT ;
        USE POWER ;
        PORT
        LAYER li ;
        RECT 1.200000 8.400000 1.500000 8.700000 ;
        END
        ANTENNADIFFAREA 1.687500 ;
    END Vdd
    PIN GND
        DIRECTION INPUT ;
        USE GROUND ;
        PORT
        LAYER li ;
        RECT 1.800000 8.400000 2.100000 8.700000 ;
        END
        ANTENNADIFFAREA 1.125000 ;
    END GND
    OBS
      LAYER li ;
         RECT 0.600000 1.800000 1.725000 7.125000 ;
    END
END _0_0std_0_0cells_0_0sky130_fd_sc_hd__inv_8

MACRO _0_0std_0_0cells_0_0sky130_fd_sc_hd__or4_1
    CLASS CORE ;
    FOREIGN _0_0std_0_0cells_0_0sky130_fd_sc_hd__or4_1 0.000000 0.000000 ;
    ORIGIN 0.000000 0.000000 ;
    SIZE 4.200000 BY 4.500000 ;
    SYMMETRY X Y ;
    SITE CoreSite ;
    PIN A
        DIRECTION INPUT ;
        USE SIGNAL ;
        PORT
        LAYER li ;
        RECT 0.600000 3.900000 0.900000 4.200000 ;
        END
    END A
    PIN B
        DIRECTION INPUT ;
        USE SIGNAL ;
        PORT
        LAYER li ;
        RECT 1.200000 3.900000 1.500000 4.200000 ;
        END
    END B
    PIN C
        DIRECTION INPUT ;
        USE SIGNAL ;
        PORT
        LAYER li ;
        RECT 1.800000 3.900000 2.100000 4.200000 ;
        END
    END C
    PIN D
        DIRECTION INPUT ;
        USE SIGNAL ;
        PORT
        LAYER li ;
        RECT 2.400000 3.900000 2.700000 4.200000 ;
        END
    END D
    PIN X
        DIRECTION OUTPUT ;
        USE SIGNAL ;
        PORT
        LAYER li ;
        RECT 0.600000 0.300000 0.900000 0.600000 ;
        END
        ANTENNADIFFAREA 0.393750 ;
    END X
    PIN Vdd
        DIRECTION INPUT ;
        USE POWER ;
        PORT
        LAYER li ;
        RECT 3.000000 3.900000 3.300000 4.200000 ;
        END
        ANTENNADIFFAREA 0.675000 ;
    END Vdd
    PIN GND
        DIRECTION INPUT ;
        USE GROUND ;
        PORT
        LAYER li ;
        RECT 3.600000 3.900000 3.900000 4.200000 ;
        END
        ANTENNADIFFAREA 0.506250 ;
    END GND
    OBS
      LAYER li ;
         RECT 0.600000 1.800000 3.525000 2.625000 ;
    END
END _0_0std_0_0cells_0_0sky130_fd_sc_hd__or4_1

MACRO _0_0std_0_0cells_0_0sky130_fd_sc_hd__clkinv_4
    CLASS CORE ;
    FOREIGN _0_0std_0_0cells_0_0sky130_fd_sc_hd__clkinv_4 0.000000 0.000000 ;
    ORIGIN 0.000000 0.000000 ;
    SIZE 2.400000 BY 5.400000 ;
    SYMMETRY X Y ;
    SITE CoreSite ;
    PIN A
        DIRECTION INPUT ;
        USE SIGNAL ;
        PORT
        LAYER li ;
        RECT 0.600000 4.800000 0.900000 5.100000 ;
        END
    END A
    PIN Y
        DIRECTION OUTPUT ;
        USE SIGNAL ;
        PORT
        LAYER li ;
        RECT 0.600000 0.300000 0.900000 0.600000 ;
        END
        ANTENNADIFFAREA 1.406250 ;
    END Y
    PIN Vdd
        DIRECTION INPUT ;
        USE POWER ;
        PORT
        LAYER li ;
        RECT 1.200000 4.800000 1.500000 5.100000 ;
        END
        ANTENNADIFFAREA 0.843750 ;
    END Vdd
    PIN GND
        DIRECTION INPUT ;
        USE GROUND ;
        PORT
        LAYER li ;
        RECT 1.800000 4.800000 2.100000 5.100000 ;
        END
        ANTENNADIFFAREA 0.562500 ;
    END GND
    OBS
      LAYER li ;
         RECT 0.600000 1.800000 1.725000 3.525000 ;
    END
END _0_0std_0_0cells_0_0sky130_fd_sc_hd__clkinv_4

MACRO _0_0std_0_0cells_0_0sky130_fd_sc_hd__xor2_4
    CLASS CORE ;
    FOREIGN _0_0std_0_0cells_0_0sky130_fd_sc_hd__xor2_4 0.000000 0.000000 ;
    ORIGIN 0.000000 0.000000 ;
    SIZE 4.800000 BY 9.000000 ;
    SYMMETRY X Y ;
    SITE CoreSite ;
    PIN A
        DIRECTION INPUT ;
        USE SIGNAL ;
        PORT
        LAYER li ;
        RECT 0.600000 8.400000 0.900000 8.700000 ;
        END
    END A
    PIN B
        DIRECTION INPUT ;
        USE SIGNAL ;
        PORT
        LAYER li ;
        RECT 1.800000 8.400000 2.100000 8.700000 ;
        END
    END B
    PIN X
        DIRECTION OUTPUT ;
        USE SIGNAL ;
        PORT
        LAYER li ;
        RECT 0.600000 0.300000 0.900000 0.600000 ;
        END
        ANTENNADIFFAREA 2.587500 ;
    END X
    PIN Vdd
        DIRECTION INPUT ;
        USE POWER ;
        PORT
        LAYER li ;
        RECT 3.000000 8.400000 3.300000 8.700000 ;
        END
        ANTENNADIFFAREA 1.350000 ;
    END Vdd
    PIN GND
        DIRECTION INPUT ;
        USE GROUND ;
        PORT
        LAYER li ;
        RECT 4.200000 8.400000 4.500000 8.700000 ;
        END
        ANTENNADIFFAREA 1.743750 ;
    END GND
    OBS
      LAYER li ;
         RECT 0.600000 1.800000 4.125000 7.125000 ;
    END
END _0_0std_0_0cells_0_0sky130_fd_sc_hd__xor2_4

MACRO welltap_svt
    CLASS CORE WELLTAP ;
    FOREIGN welltap_svt 0.000000 0.000000 ;
    ORIGIN 0.000000 0.000000 ;
    SIZE 1.200000 BY 2.100000 ;
    SYMMETRY X Y ;
    SITE CoreSite ;
    PIN Vdd
        DIRECTION INPUT ;
        USE POWER ;
        PORT
        LAYER li ;
        RECT 0.600000 1.500000 0.900000 1.800000 ;
        END
    END Vdd
    PIN GND
        DIRECTION INPUT ;
        USE GROUND ;
        PORT
        LAYER li ;
        RECT 0.600000 0.300000 0.900000 0.600000 ;
        END
    END GND
END welltap_svt

